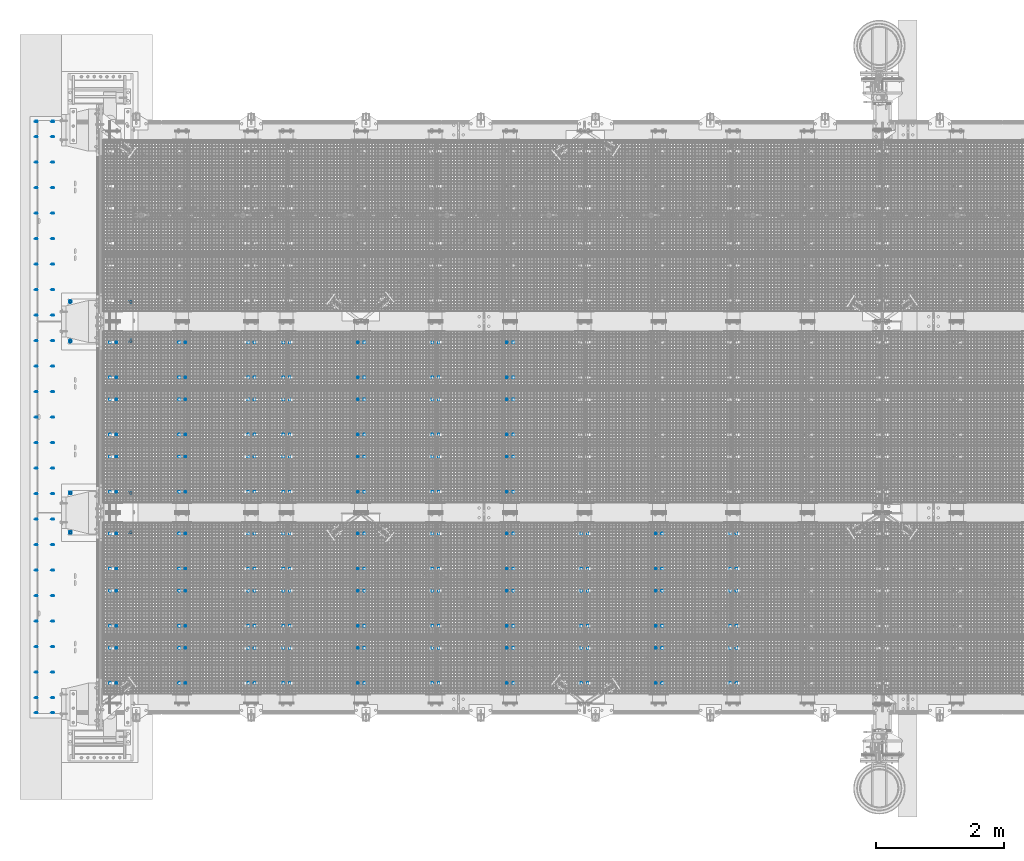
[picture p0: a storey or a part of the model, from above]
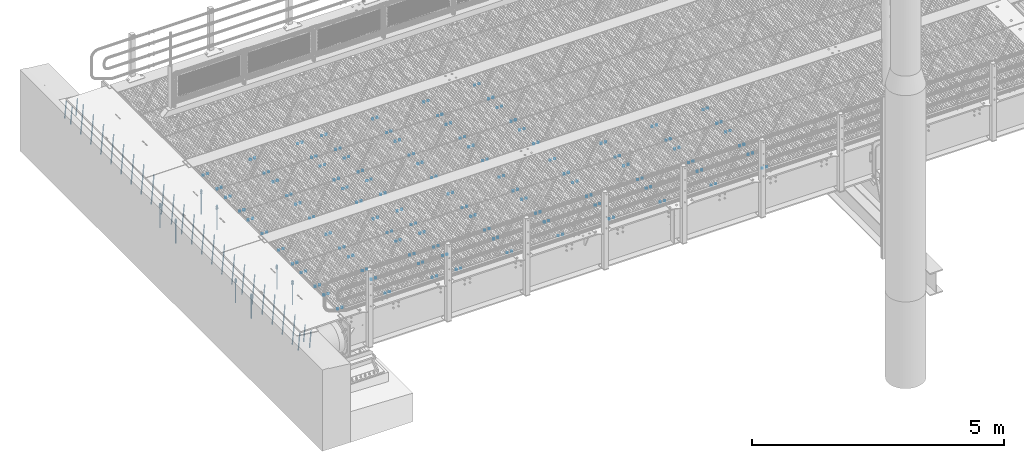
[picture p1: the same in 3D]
Properties of the parts of a building model (IFC2X3), part 1 of 2

# File
Description: ViewDefinition[CoordinationView_V2.0], ExchangeRequirement[Structural, SurfaceGeometry], Option [GridExport:On], Option [Assemblies:Off], Option [Bolts:On], Option [Rebars:On], Option [PourObjects:Off], Option [Welds:Off], Option [SurfaceTreatments:On], Option [LocationBy:0], Option [ViewColors:Off], Option [SectionedSpine:Off], Option [PropertySets:On], Option [Export all:Off]
File name: Brattvåg 9x18 ferjekaibru med gitterrister_2026-06-01.ifc
Time: 2026-06-01T10:39:22
Author: NORCONSULTAD\egj
Organization: Structural Designer
Written by: IFC Parser Version: 3.14.0
Made in: Tekla Structures 2025 Service Pack 6, IFC Export Version: 4.0.0.0 Dec 9 2025

# IfcBuildingStorey, Undefined
In: Undefined
Elevation: 0 mm

# IfcBeam: 12*12 (8)
In: Undefined
Description: 12*12; Material: STEEL/S355N
Tekla Common - Class: 5; Phase: 13
Tekla Quantity - Width: 12 mm; Height: 12 mm; Volume: 0 m3
BeamBaseQuantities - OuterSurfaceArea: 0 m2; NetVolume: 0 m3
Name | Top elevation | Bottom elevation | Tekla Quantity, Length (mm) = BeamBaseQuantities, Length (mm) | Net surface area (m2) | Area per tons (m2) | Gross footprint area (m2) | Weight (kg) | NetWeight (kg) | Slope (rad)
4 x STÅLBJELKE | -0.358 | -0.532 | 174 | 0.009 | 43.927 | 0 | 0.2 | 0.2 | 1.5708
2 x STÅLBJELKE | -0.532 | -0.544 | 625 | 0.03 | 42.87 | 0.008 | 0.71 | 0.7 | 0
2 x STÅLBJELKE | -0.346 | -0.358 | 625 | 0.03 | 42.87 | 0.008 | 0.71 | 0.7 | 0

# IfcBeam: 120*5 (1503)
In: Undefined
Description: 120*5; Material: STEEL/S355J2
Tekla Common - Class: 3; Phase: 3; Top elevation: +0.000; Bottom elevation: -0.120
Tekla Quantity - Width: 5 mm; Height: 120 mm
BeamBaseQuantities - NetVolume: 0 m3
Pset_BeamCommon - Slope: 0 rad
Name | Tekla Quantity, Length (mm) = BeamBaseQuantities, Length (mm) | Net surface area (m2) | Area per tons (m2) | Gross footprint area (m2) | Volume (m3) | Weight (kg) | OuterSurfaceArea (m2) | NetWeight (kg)
153 x GRATING | 535 | 0.135 | 54.618 | 0.002 | 0 | 2.47 | 0.1 | 2.5
18 x GRATING | 545 | 0.137 | 53.546 | 0.003 | 0 | 2.57 | 0.1 | 2.6
135 x GRATING | 878 | 0.221 | 53.369 | 0.004 | 0.001 | 4.14 | 0.2 | 4.1
918 x GRATING | 2320 | 0.581 | 54.31 | 0.01 | 0.001 | 10.7 | 0.6 | 10.7
108 x GRATING | 2330 | 0.584 | 53.188 | 0.012 | 0.001 | 10.97 | 0.6 | 11
153 x GRATING | 2298 | 0.575 | 54.344 | 0.01 | 0.001 | 10.59 | 0.6 | 10.7
18 x GRATING | 2308 | 0.578 | 53.209 | 0.012 | 0.001 | 10.86 | 0.6 | 11

# IfcBeam: 20*300 (2)
In: Undefined
Description: 20*300; Material: STEEL/S355N
Tekla Common - Class: 4; Phase: 10; Top elevation: -0.015; Bottom elevation: -0.185
Tekla Quantity - Length: 958.6 mm; Width: 300 mm; Height: 20 mm; Net surface area: 0.627 m2; Area per tons: 13.855 m2; Gross footprint area: 0 m2; Volume: 0.006 m3; Weight: 45.27 kg
BeamBaseQuantities - Length: 958.6 mm; OuterSurfaceArea: 0.6 m2; NetVolume: 0 m3; NetWeight: 45.3 kg
Pset_BeamCommon - Slope: 0 rad

# IfcBeam: 25*5 (3276)
In: Undefined
Description: 25*5; Material: STEEL/S355J2
Tekla Common - Class: 3; Phase: 3; Top elevation: +0.000; Bottom elevation: -0.025
Tekla Quantity - Width: 5 mm; Height: 25 mm; Volume: 0 m3
BeamBaseQuantities - NetVolume: 0 m3
Pset_BeamCommon - Slope: 0 rad
Name | Tekla Quantity, Length (mm) = BeamBaseQuantities, Length (mm) | Net surface area (m2) | Area per tons (m2) | Gross footprint area (m2) | Weight (kg) | OuterSurfaceArea (m2) | NetWeight (kg)
2844 x GRATING | 878 | 0.053 | 61.437 | 0.004 | 0.86 | 0.1 | 0.9
288 x GRATING | 141.5 | 0.009 | 62.947 | 0.001 | 0.14 | 0 | 0.1
144 x GRATING | 505 | 0.031 | 61.651 | 0.003 | 0.5 | 0 | 0.5

# IfcBeam: 60*10 (9)
In: Undefined
Description: 60*10; Material: STEEL/S355J2
Tekla Common - Class: 3; Phase: 3; Top elevation: -0.100; Bottom elevation: -0.160
Tekla Quantity - Length: 888 mm; Width: 10 mm; Height: 60 mm; Net surface area: 0.126 m2; Area per tons: 30.011 m2; Gross footprint area: 0.01 m2; Volume: 0.001 m3; Weight: 4.18 kg
BeamBaseQuantities - Length: 888 mm; OuterSurfaceArea: 0.1 m2; NetVolume: 0 m3; NetWeight: 4.1 kg
Pset_BeamCommon - Slope: 0 rad

# IfcBeam: CFCHS130*29 (52)
In: Undefined
Description: CFCHS130*29; Material: STEEL/EN 1.4462
Tekla Common - Class: 6; Phase: 4
Tekla Quantity - Length: 10 mm; Width: 130 mm; Height: 130 mm; Net surface area: 0.016 m2; Area per tons: 21.625 m2; Gross footprint area: 0 m2; Volume: 0 m3; Weight: 0.73 kg
BeamBaseQuantities - Length: 10 mm; OuterSurfaceArea: 0 m2; NetVolume: 0 m3; NetWeight: 0.7 kg
Pset_BeamCommon - Slope: 0 rad
Name | Top elevation | Bottom elevation
48 x BEAM | -0.380 | -0.510
4 x BEAM | -0.360 | -0.490

# IfcBeam: D10 (2)
In: Undefined
Description: D10; Material: STEEL/Steel_Undefined
Tekla Common - Class: 3; Phase: 6; Top elevation: +0.208; Bottom elevation: +0.068
Tekla Quantity - Length: 311.4 mm; Width: 10 mm; Height: 10 mm; Net surface area: 0.009 m2; Area per tons: 55.326 m2; Gross footprint area: 0 m2; Volume: 0 m3; Weight: 0.19 kg
BeamBaseQuantities - Length: 311.4 mm; OuterSurfaceArea: 0 m2; NetVolume: 0 m3; NetWeight: 0.2 kg
Pset_BeamCommon - Slope: 0 rad

# IfcBeam: D100 (4)
In: Undefined
Description: D100; Material: STEEL/Steel_Undefined
Tekla Common - Class: 3; Phase: 6; Top elevation: +5.449; Bottom elevation: +5.349
Tekla Quantity - Length: 15 mm; Width: 100 mm; Height: 100 mm; Net surface area: 0.013 m2; Area per tons: 40.078 m2; Gross footprint area: 0 m2; Volume: 0 m3; Weight: 0.36 kg
BeamBaseQuantities - Length: 15 mm; OuterSurfaceArea: 0 m2; NetVolume: 0 m3; NetWeight: 0.3 kg
Pset_BeamCommon - Slope: 0 rad

# IfcBeam: D110 (4)
In: Undefined
Description: D110; Material: STEEL/Steel_Undefined
Tekla Common - Class: 3; Phase: 6; Top elevation: +0.185; Bottom elevation: +0.075
Tekla Quantity - Length: 15 mm; Width: 110 mm; Height: 110 mm; Net surface area: 0.024 m2; Area per tons: 21.675 m2; Gross footprint area: 0 m2; Volume: 0 m3; Weight: 1.1 kg
BeamBaseQuantities - Length: 15 mm; OuterSurfaceArea: 0 m2; NetVolume: 0 m3; NetWeight: 1.1 kg
Pset_BeamCommon - Slope: 0 rad

# IfcBeam: D160 (2)
In: Undefined
Description: D160; Material: MISCELLANEOUS/UNDEFINED
Tekla Common - Class: 4; Phase: 7; Top elevation: -0.843; Bottom elevation: -1.003
Tekla Quantity - Length: 125 mm; Width: 160 mm; Height: 160 mm; Net surface area: 0.102 m2; Area per tons: 0 m2; Gross footprint area: 0 m2; Volume: 0.002 m3; Weight: 0 kg
BeamBaseQuantities - Length: 125 mm; OuterSurfaceArea: 0.1 m2; NetVolume: 0 m3; NetWeight: 0 kg
Pset_BeamCommon - Slope: 0 rad

# IfcBeam: D20 (3)
In: Undefined
Description: D20; Material: STEEL/S355N
Tekla Common - Class: 4; Phase: 11; Top elevation: -0.025; Bottom elevation: -0.045
Tekla Quantity - Width: 20 mm; Height: 20 mm; Gross footprint area: 0 m2; Volume: 0.001 m3
BeamBaseQuantities - OuterSurfaceArea: 0.2 m2; NetVolume: 0 m3
Pset_BeamCommon - Slope: 0 rad
Name | Tekla Quantity, Length (mm) = BeamBaseQuantities, Length (mm) | Net surface area (m2) | Area per tons (m2) | Weight (kg) | NetWeight (kg)
2 x STÅLBJELKE | 3145 | 0.193 | 27.658 | 6.98 | 7
STÅLBJELKE | 2990 | 0.184 | 27.662 | 6.64 | 6.6

# IfcBeam: D200 (6)
In: Undefined
Description: D200
Tekla Quantity - Width: 200 mm
BeamBaseQuantities - NetVolume: 0 m3
Name | Material | Class | Phase | Top elevation | Bottom elevation | Tekla Quantity, Length (mm) = BeamBaseQuantities, Length (mm) | Height (mm) | Net surface area (m2) | Area per tons (m2) | Gross footprint area (m2) | Volume (m3) | Weight (kg) | OuterSurfaceArea (m2) | NetWeight (kg) | Slope (rad)
2 x HEISTÅRN | STEEL/Steel_Undefined | 3 | 6 | +5.249 | +5.199 | 50 | 200 | 0.093 | 7.665 | 0.031 | 0.002 | 12.19 | 0.1 | 12.2 | 1.5708
2 x STÅLBJELKE | STEEL/S355N | 2 | 5 | -0.828 | -1.028 | 770 | 200 | 0.521 | 3.171 | 0 | 0.022 | 164.23 | 0.5 | 164.2 | 0
2 x STÅLBJELKE | STEEL/S355N | 2 | 5 | -0.890 | -1.028 | 280 | 138 | 0.207 | 4.108 | 0.051 | 0.006 | 50.33 | 0.2 | 50.3 | 0

# IfcBeam: D3 (535)
In: Undefined
Description: D3; Material: STEEL/S235J0
Tekla Common - Class: 3; Phase: 9
Tekla Quantity - Width: 3 mm; Height: 2.6 mm; Volume: 0 m3
BeamBaseQuantities - OuterSurfaceArea: 0 m2; NetVolume: 0 m3
Name | Top elevation | Bottom elevation | Tekla Quantity, Length (mm) = BeamBaseQuantities, Length (mm) | Net surface area (m2) | Area per tons (m2) | Gross footprint area (m2) | Weight (kg) | NetWeight (kg) | Slope (rad)
26 x BEAM | +0.866 | +0.373 | 493 | 0.004 | 196.644 | 0 | 0.02 | 0 | 1.5708
BEAM | +0.394 | +0.391 | 921.4 | 0.008 | 196.404 | 0.001 | 0.04 | 0 | 0
BEAM | +0.429 | +0.426 | 921.4 | 0.008 | 196.404 | 0.001 | 0.04 | 0 | 0
BEAM | +0.464 | +0.461 | 921.4 | 0.008 | 196.404 | 0.001 | 0.04 | 0 | 0
BEAM | +0.499 | +0.496 | 921.4 | 0.008 | 196.404 | 0.001 | 0.04 | 0 | 0
BEAM | +0.534 | +0.531 | 921.4 | 0.008 | 196.404 | 0.001 | 0.04 | 0 | 0
BEAM | +0.569 | +0.566 | 921.4 | 0.008 | 196.404 | 0.001 | 0.04 | 0 | 0
BEAM | +0.604 | +0.601 | 921.4 | 0.008 | 196.404 | 0.001 | 0.04 | 0 | 0
BEAM | +0.639 | +0.636 | 921.4 | 0.008 | 196.404 | 0.001 | 0.04 | 0 | 0
BEAM | +0.674 | +0.671 | 921.4 | 0.008 | 196.404 | 0.001 | 0.04 | 0 | 0
BEAM | +0.709 | +0.706 | 921.4 | 0.008 | 196.404 | 0.001 | 0.04 | 0 | 0
BEAM | +0.744 | +0.741 | 921.4 | 0.008 | 196.404 | 0.001 | 0.04 | 0 | 0
BEAM | +0.779 | +0.776 | 921.4 | 0.008 | 196.404 | 0.001 | 0.04 | 0 | 0
BEAM | +0.814 | +0.811 | 921.4 | 0.008 | 196.404 | 0.001 | 0.04 | 0 | 0
BEAM | +0.849 | +0.846 | 921.4 | 0.008 | 196.404 | 0.001 | 0.04 | 0 | 0
369 x BEAM | +0.867 | +0.374 | 493 | 0.004 | 196.644 | 0 | 0.02 | 0 | 1.5708
9 x BEAM | +0.394 | +0.391 | 1423 | 0.013 | 196.307 | 0.002 | 0.07 | 0.1 | 0
9 x BEAM | +0.429 | +0.426 | 1423 | 0.013 | 196.307 | 0.002 | 0.07 | 0.1 | 0
9 x BEAM | +0.464 | +0.461 | 1423 | 0.013 | 196.307 | 0.002 | 0.07 | 0.1 | 0
9 x BEAM | +0.499 | +0.496 | 1423 | 0.013 | 196.307 | 0.002 | 0.07 | 0.1 | 0
9 x BEAM | +0.534 | +0.531 | 1423 | 0.013 | 196.307 | 0.002 | 0.07 | 0.1 | 0
9 x BEAM | +0.569 | +0.566 | 1423 | 0.013 | 196.307 | 0.002 | 0.07 | 0.1 | 0
9 x BEAM | +0.604 | +0.601 | 1423 | 0.013 | 196.307 | 0.002 | 0.07 | 0.1 | 0
9 x BEAM | +0.639 | +0.636 | 1423 | 0.013 | 196.307 | 0.002 | 0.07 | 0.1 | 0
9 x BEAM | +0.674 | +0.671 | 1423 | 0.013 | 196.307 | 0.002 | 0.07 | 0.1 | 0
9 x BEAM | +0.709 | +0.706 | 1423 | 0.013 | 196.307 | 0.002 | 0.07 | 0.1 | 0
9 x BEAM | +0.744 | +0.741 | 1423 | 0.013 | 196.307 | 0.002 | 0.07 | 0.1 | 0
9 x BEAM | +0.779 | +0.776 | 1423 | 0.013 | 196.307 | 0.002 | 0.07 | 0.1 | 0
9 x BEAM | +0.814 | +0.811 | 1423 | 0.013 | 196.307 | 0.002 | 0.07 | 0.1 | 0
9 x BEAM | +0.849 | +0.846 | 1423 | 0.013 | 196.307 | 0.002 | 0.07 | 0.1 | 0

# IfcBeam: D30 (4)
In: Undefined
Description: D30; Material: STEEL/Steel_Undefined
Tekla Common - Class: 3; Phase: 6; Top elevation: +0.145; Bottom elevation: +0.115
Tekla Quantity - Length: 15 mm; Width: 30 mm; Height: 30 mm; Net surface area: 0.003 m2; Area per tons: 34.569 m2; Gross footprint area: 0 m2; Volume: 0 m3; Weight: 0.07 kg
BeamBaseQuantities - Length: 15 mm; OuterSurfaceArea: 0 m2; NetVolume: 0 m3; NetWeight: 0.1 kg
Pset_BeamCommon - Slope: 0 rad

# IfcBeam: D32 (30)
In: Undefined
Description: D32; Material: STEEL/Steel_Undefined
Tekla Common - Class: 3; Phase: 6
Tekla Quantity - Width: 32 mm; Height: 32 mm; Gross footprint area: 0 m2; Volume: 0 m3; Weight: 2.04 kg
BeamBaseQuantities - OuterSurfaceArea: 0 m2; NetVolume: 0 m3; NetWeight: 2 kg
Name | Top elevation | Bottom elevation | Tekla Quantity, Length (mm) = BeamBaseQuantities, Length (mm) | Net surface area (m2) | Area per tons (m2) | Slope (rad)
2 x HEISTÅRN | +0.389 | +0.230 | 243.2 | 0.035 | 17.341 | 0.04047
2 x HEISTÅRN | +0.580 | +0.421 | 243.2 | 0.035 | 17.341 | 0.04047
2 x HEISTÅRN | +0.772 | +0.612 | 243.2 | 0.035 | 17.341 | 0.04047
2 x HEISTÅRN | +0.963 | +0.803 | 243.2 | 0.035 | 17.341 | 0.04047
2 x HEISTÅRN | +1.154 | +0.994 | 243.2 | 0.035 | 17.341 | 0.04047
2 x HEISTÅRN | +1.345 | +1.186 | 243.2 | 0.035 | 17.341 | 0.04047
2 x HEISTÅRN | +1.536 | +1.377 | 243.2 | 0.035 | 17.341 | 0.04047
2 x HEISTÅRN | +0.485 | +0.326 | 242.8 | 0.034 | 16.588 | 0.08742
2 x HEISTÅRN | +0.676 | +0.517 | 242.8 | 0.034 | 16.588 | 0.08742
2 x HEISTÅRN | +0.867 | +0.708 | 242.8 | 0.034 | 16.588 | 0.08742
2 x HEISTÅRN | +1.058 | +0.899 | 242.8 | 0.034 | 16.588 | 0.08742
2 x HEISTÅRN | +1.250 | +1.090 | 242.8 | 0.034 | 16.588 | 0.08742
2 x HEISTÅRN | +1.441 | +1.281 | 242.8 | 0.034 | 16.588 | 0.08742
2 x HEISTÅRN | +1.632 | +1.472 | 242.8 | 0.034 | 16.588 | 0.08742
2 x HEISTÅRN | +1.727 | +1.568 | 243.2 | 0.035 | 17.341 | 0.04047

# IfcBeam: D38 (4)
In: Undefined
Description: D38; Material: STEEL/Steel_Undefined
Tekla Common - Class: 3; Phase: 6
Tekla Quantity - Length: 420.3 mm; Width: 38 mm; Height: 38 mm; Net surface area: 0.063 m2; Area per tons: 13.938 m2; Gross footprint area: 0 m2; Volume: 0.001 m3; Weight: 4.54 kg
BeamBaseQuantities - Length: 420.3 mm; OuterSurfaceArea: 0.1 m2; NetVolume: 0 m3; NetWeight: 4.5 kg
Pset_BeamCommon - Slope: 0.08971 rad
Name | Top elevation | Bottom elevation
2 x HEISTÅRN | +0.309 | +0.066
2 x HEISTÅRN | +1.900 | +1.657

# IfcBeam: D488 (2)
In: Undefined
Description: D488; Material: STEEL/S355N
Tekla Common - Class: 4; Phase: 10; Top elevation: -0.015; Bottom elevation: -0.503
Tekla Quantity - Length: 20 mm; Width: 298 mm; Height: 488 mm; Net surface area: 0.265 m2; Area per tons: 14.182 m2; Gross footprint area: 0 m2; Volume: 0.002 m3; Weight: 18.7 kg
BeamBaseQuantities - Length: 20 mm; OuterSurfaceArea: 0.3 m2; NetVolume: 0 m3; NetWeight: 18.7 kg
Pset_BeamCommon - Slope: 0.00024 rad

# IfcBeam: D60, STÅLBJELKE
In: Undefined
Description: D60; Material: STEEL/S355J2+N
Tekla Common - Class: 4; Phase: 10; Top elevation: -0.453; Bottom elevation: -0.513
Tekla Quantity - Length: 9000 mm; Width: 60 mm; Height: 60 mm; Net surface area: 1.691 m2; Area per tons: 8.687 m2; Gross footprint area: 0 m2; Volume: 0.025 m3; Weight: 194.66 kg
BeamBaseQuantities - Length: 9000 mm; OuterSurfaceArea: 1.7 m2; NetVolume: 0 m3; NetWeight: 194.7 kg
Pset_BeamCommon - Slope: 0 rad

# IfcBeam: D70 (30)
In: Undefined
Description: D70
Tekla Quantity - Width: 70 mm; Height: 70 mm; Gross footprint area: 0 m2
BeamBaseQuantities - OuterSurfaceArea: 0 m2; NetVolume: 0 m3
Pset_BeamCommon - Slope: 0 rad
Name | Material | Class | Phase | Top elevation | Bottom elevation | Tekla Quantity, Length (mm) = BeamBaseQuantities, Length (mm) | Net surface area (m2) | Area per tons (m2) | Volume (m3) | Weight (kg) | NetWeight (kg)
24 x BEAM | STEEL/EN 1.4462 | 6 | 4 | -0.410 | -0.480 | 200 | 0.048 | 8.237 | 0.001 | 5.79 | 5.8
2 x BEAM | STEEL/EN 1.4462 | 6 | 4 | -0.390 | -0.460 | 200 | 0.048 | 8.237 | 0.001 | 5.79 | 5.8
2 x HEISTÅRN | STEEL/Steel_Undefined | 3 | 6 | +0.175 | +0.105 | 140 | 0.038 | 9.242 | 0.001 | 4.12 | 4.1
2 x HEISTÅRN | STEEL/Steel_Undefined | 3 | 6 | +1.862 | +1.792 | 130 | 0.036 | 9.382 | 0 | 3.84 | 3.8

# IfcBeam: D708 (2)
In: Undefined
Description: D708; Material: STEEL/Steel_Undefined
Tekla Common - Class: 3; Phase: 6; Top elevation: +6.270; Bottom elevation: +6.260
Tekla Quantity - Length: 10 mm; Width: 708 mm; Height: 708 mm; Net surface area: 0.807 m2; Area per tons: 26.199 m2; Gross footprint area: 0.392 m2; Volume: 0.004 m3; Weight: 30.8 kg
BeamBaseQuantities - Length: 10 mm; OuterSurfaceArea: 0.8 m2; NetVolume: 0 m3; NetWeight: 30.8 kg
Pset_BeamCommon - Slope: 1.5708 rad

# IfcBeam: D78 (2)
In: Undefined
Description: D78; Material: STEEL/Steel_Undefined
Tekla Common - Class: 3; Phase: 6; Top elevation: +5.438; Bottom elevation: +5.360
Tekla Quantity - Length: 250 mm; Width: 78 mm; Height: 78 mm; Net surface area: 0.07 m2; Area per tons: 7.68 m2; Gross footprint area: 0 m2; Volume: 0.001 m3; Weight: 9.14 kg
BeamBaseQuantities - Length: 250 mm; OuterSurfaceArea: 0.1 m2; NetVolume: 0 m3; NetWeight: 9.1 kg
Pset_BeamCommon - Slope: 0 rad

# IfcBeam: D80 (4)
In: Undefined
Description: D80; Material: STEEL/Steel_Undefined
Tekla Common - Class: 3; Phase: 6
Tekla Quantity - Width: 80 mm; Height: 80 mm; Gross footprint area: 0 m2
BeamBaseQuantities - NetVolume: 0 m3
Name | Top elevation | Bottom elevation | Tekla Quantity, Length (mm) = BeamBaseQuantities, Length (mm) | Net surface area (m2) | Area per tons (m2) | Volume (m3) | Weight (kg) | OuterSurfaceArea (m2) | NetWeight (kg) | Slope (rad)
2 x HEISTÅRN | +0.170 | +0.090 | 170 | 0.053 | 7.993 | 0.001 | 6.54 | 0.1 | 6.5 | 0
2 x HEISTÅRN | +5.199 | +0.205 | 4993.9 | 1.257 | 6.545 | 0.024 | 192.02 | 1.3 | 192 | 1.55878

# IfcBeam: D800 (4)
In: Undefined
Description: D800; Material: MISCELLANEOUS/NULLVEKT
Tekla Common - Class: 4; Phase: 12; Top elevation: -0.115; Bottom elevation: -0.915
Tekla Quantity - Length: 25 mm; Width: 800 mm; Height: 800 mm; Net surface area: 1.065 m2; Area per tons: 0 m2; Gross footprint area: 0 m2; Volume: 0.014 m3; Weight: 0 kg
BeamBaseQuantities - Length: 25 mm; OuterSurfaceArea: 1.1 m2; NetVolume: 0 m3; NetWeight: 0 kg
Pset_BeamCommon - Slope: 0 rad

# IfcBeam: ELD70*70*65*65 (2)
In: Undefined
Description: ELD70*70*65*65; Material: STEEL/Steel_Undefined
Tekla Common - Class: 3; Phase: 6; Top elevation: +0.175; Bottom elevation: +0.105
Tekla Quantity - Length: 10 mm; Width: 70 mm; Height: 70 mm; Net surface area: 0.009 m2; Area per tons: 33.422 m2; Gross footprint area: 0 m2; Volume: 0 m3; Weight: 0.27 kg
BeamBaseQuantities - Length: 10 mm; OuterSurfaceArea: 0 m2; NetVolume: 0 m3; NetWeight: 0.3 kg
Pset_BeamCommon - Slope: 0 rad

# IfcBeam: EPD660*660*490*490*100 (4)
In: Undefined
Description: EPD660*660*490*490*100; Material: MISCELLANEOUS/NULLVEKT
Tekla Common - Class: 4; Phase: 12; Top elevation: -0.185; Bottom elevation: -0.845
Tekla Quantity - Length: 350 mm; Width: 660 mm; Height: 660 mm; Net surface area: 0.808 m2; Area per tons: 0 m2; Gross footprint area: 0 m2; Volume: 0.053 m3; Weight: 0 kg
BeamBaseQuantities - Length: 350 mm; OuterSurfaceArea: 0.8 m2; NetVolume: 0.1 m3; NetWeight: 0 kg
Pset_BeamCommon - Slope: 0 rad

# IfcBeam: HEA600, STÅLBJELKE
In: Undefined
Description: HEA600; Material: STEEL/S355J2+N
Tekla Common - Class: 5; Phase: 13; Top elevation: -0.890; Bottom elevation: -1.480
Tekla Quantity - Length: 10130 mm; Width: 300 mm; Height: 590 mm; Net surface area: 23.884 m2; Area per tons: 12.981 m2; Gross footprint area: 3.022 m2; Volume: 0.229 m3; Weight: 1801.14 kg
BeamBaseQuantities - Length: 10130 mm; OuterSurfaceArea: 23.4 m2; NetVolume: 0.2 m3; NetWeight: 1747.7 kg
Pset_BeamCommon - Slope: 0 rad

# IfcBeam: HEA900 (4)
In: Undefined
Description: HEA900; Material: STEEL/S355J2+N
Tekla Common - Class: 2; Phase: 5; Top elevation: +0.000; Bottom elevation: -0.890
Tekla Quantity - Length: 16807 mm; Width: 300 mm; Height: 890 mm; Net surface area: 49.61 m2; Area per tons: 11.509 m2; Gross footprint area: 5.042 m2; Volume: 0.54 m3; Weight: 4235.11 kg
BeamBaseQuantities - Length: 16807 mm; OuterSurfaceArea: 48.7 m2; NetVolume: 0.5 m3; NetWeight: 4126.9 kg
Pset_BeamCommon - Slope: 0 rad

# IfcBeam: HEB180 (13)
In: Undefined
Description: HEB180; Material: STEEL/S355J2+N
Tekla Common - Class: 3; Phase: 4; Top elevation: -0.355; Bottom elevation: -0.535
Tekla Quantity - Width: 180 mm; Height: 180 mm; Area per tons: 20.246 m2
BeamBaseQuantities - NetVolume: 0 m3
Pset_BeamCommon - Slope: 0 rad
Name | Tekla Quantity, Length (mm) = BeamBaseQuantities, Length (mm) | Net surface area (m2) | Gross footprint area (m2) | Volume (m3) | Weight (kg) | OuterSurfaceArea (m2) | NetWeight (kg)
2 x STÅLBJELKE | 4354.3 | 4.641 | 0.784 | 0.028 | 223.03 | 4.5 | 216.4
2 x STÅLBJELKE | 3414.8 | 3.643 | 0.615 | 0.022 | 174.91 | 3.5 | 169.7
5 x STÅLBJELKE | 2200 | 2.351 | 0.396 | 0.014 | 112.69 | 2.3 | 109.4
2 x STÅLBJELKE | 3853.3 | 4.109 | 0.694 | 0.025 | 197.37 | 4 | 191.5
2 x STÅLBJELKE | 4051.6 | 4.32 | 0.729 | 0.026 | 207.53 | 4.2 | 201.4

# IfcBeam: HEB200 (50)
In: Undefined
Description: HEB200; Material: STEEL/S355J2+N
Tekla Quantity - Width: 200 mm; Height: 200 mm; Area per tons: 18.779 m2
BeamBaseQuantities - NetVolume: 0 m3
Pset_BeamCommon - Slope: 0 rad
Name | Class | Phase | Top elevation | Bottom elevation | Tekla Quantity, Length (mm) = BeamBaseQuantities, Length (mm) | Net surface area (m2) | Gross footprint area (m2) | Volume (m3) | Weight (kg) | OuterSurfaceArea (m2) | NetWeight (kg)
2 x STÅLBJELKE | 5 | 13 | -0.345 | -0.545 | 387 | 0.472 | 0.077 | 0.003 | 23.72 | 0.3 | 22.9
48 x STÅLBJELKE | 4 | 2 | -0.120 | -0.320 | 2954 | 3.507 | 0.591 | 0.023 | 181.06 | 3.5 | 174.6

# IfcBeam: HEB550, BEAM
In: Undefined
Description: HEB550; Material: STEEL/Steel_Undefined
Tekla Common - Class: 3; Phase: 6; Top elevation: -2.326; Bottom elevation: -2.876
Tekla Quantity - Length: 12497 mm; Width: 300 mm; Height: 550 mm; Net surface area: 28.418 m2; Area per tons: 11.15 m2; Gross footprint area: 3.749 m2; Volume: 0.318 m3; Weight: 2492.76 kg
BeamBaseQuantities - Length: 12497 mm; OuterSurfaceArea: 27.8 m2; NetVolume: 0.3 m3; NetWeight: 2431 kg
Pset_BeamCommon - Slope: 0 rad

# IfcBeam: L100*65*10 (3)
In: Undefined
Description: L100*65*10; Material: STEEL/S355J2
Tekla Common - Class: 4; Phase: 10; Top elevation: -0.130; Bottom elevation: -0.230
Tekla Quantity - Length: 2660 mm; Width: 65 mm; Height: 100 mm; Net surface area: 0.881 m2; Area per tons: 26.213 m2; Gross footprint area: 0.027 m2; Volume: 0.004 m3; Weight: 32.57 kg
BeamBaseQuantities - Length: 2660 mm; OuterSurfaceArea: 0.8 m2; NetVolume: 0 m3; NetWeight: 32.4 kg
Pset_BeamCommon - Slope: 0 rad

# IfcBeam: L60*6 (9)
In: Undefined
Description: L60*6; Material: STEEL/S355J2
Tekla Common - Class: 4; Phase: 10; Top elevation: -0.185; Bottom elevation: -0.245
Tekla Quantity - Length: 2660 mm; Width: 60 mm; Height: 60 mm; Net surface area: 0.64 m2; Area per tons: 42.954 m2; Gross footprint area: 0.16 m2; Volume: 0.002 m3; Weight: 14.43 kg
BeamBaseQuantities - Length: 2660 mm; OuterSurfaceArea: 0.6 m2; NetVolume: 0 m3; NetWeight: 14.3 kg
Pset_BeamCommon - Slope: 0 rad

# IfcBeam: PL20*251 (2)
In: Undefined
Description: PL20*251; Material: STEEL/S355N
Tekla Common - Class: 4; Phase: 10; Top elevation: -0.031; Bottom elevation: -0.484
Tekla Quantity - Length: 453 mm; Width: 20 mm; Height: 251 mm; Net surface area: 0.202 m2; Area per tons: 14.465 m2; Gross footprint area: 0 m2; Volume: 0.002 m3; Weight: 13.93 kg
BeamBaseQuantities - Length: 453 mm; OuterSurfaceArea: 0.2 m2; NetVolume: 0 m3; NetWeight: 13.9 kg
Pset_BeamCommon - Slope: 1.57042 rad

# IfcBeam: PL3*1000 (2)
In: Undefined
Description: PL3*1000; Material: STEEL/S355J2+N
Tekla Common - Class: 4; Phase: 9; Top elevation: +1.187; Bottom elevation: +0.187
Tekla Quantity - Length: 153.7 mm; Width: 3 mm; Height: 1000 mm; Net surface area: 0.314 m2; Area per tons: 86.902 m2; Gross footprint area: 0 m2; Volume: 0 m3; Weight: 3.63 kg
BeamBaseQuantities - Length: 153.7 mm; OuterSurfaceArea: 0.3 m2; NetVolume: 0 m3; NetWeight: 3.6 kg
Pset_BeamCommon - Slope: 0 rad

# IfcBeam: PL3*35 (40)
In: Undefined
Description: PL3*35; Material: STEEL/S235J0
Tekla Common - Class: 120; Phase: 9
Tekla Quantity - Width: 3 mm; Height: 35 mm; Volume: 0 m3
BeamBaseQuantities - NetVolume: 0 m3
Name | Top elevation | Bottom elevation | Tekla Quantity, Length (mm) = BeamBaseQuantities, Length (mm) | Net surface area (m2) | Area per tons (m2) | Gross footprint area (m2) | Weight (kg) | OuterSurfaceArea (m2) | NetWeight (kg) | Slope (rad)
9 x STÅLBJELKE | +0.901 | +0.338 | 563 | 0.04 | 92.887 | 0 | 0.44 | 0 | 0.3 | 1.57079
9 x STÅLBJELKE | +0.901 | +0.339 | 562.9 | 0.04 | 92.888 | 0 | 0.44 | 0 | 0.3 | 1.5708
9 x STÅLBJELKE | +0.901 | +0.866 | 1493 | 0.111 | 92.452 | 0.004 | 1.2 | 0.1 | 1.2 | 0
STÅLBJELKE | +0.902 | +0.339 | 563 | 0.04 | 92.887 | 0 | 0.44 | 0 | 0.3 | 1.57079
STÅLBJELKE | +0.901 | +0.338 | 562.9 | 0.04 | 92.888 | 0 | 0.44 | 0 | 0.3 | 1.5708
STÅLBJELKE | +0.902 | +0.866 | 991.4 | 0.073 | 92.582 | 0.003 | 0.79 | 0.1 | 0.7 | 0.00006
9 x STÅLBJELKE | +0.374 | +0.338 | 1493 | 0.111 | 92.452 | 0.004 | 1.2 | 0.1 | 1.2 | 0.00004
STÅLBJELKE | +0.374 | +0.338 | 991.4 | 0.073 | 92.582 | 0.003 | 0.79 | 0.1 | 0.7 | 0

# IfcBeam: RHS100*10 (20)
In: Undefined
Description: RHS100*10; Material: STEEL/S355J2H
Tekla Common - Class: 11; Phase: 8; Top elevation: +1.010; Bottom elevation: -0.845
Tekla Quantity - Length: 1855 mm; Width: 100 mm; Height: 100 mm; Net surface area: 0.746 m2; Area per tons: 13.651 m2; Gross footprint area: 0.004 m2; Volume: 0.006 m3; Weight: 50.82 kg
BeamBaseQuantities - Length: 1855 mm; OuterSurfaceArea: 0.6 m2; NetVolume: 0 m3; NetWeight: 52.4 kg
Pset_BeamCommon - Slope: 1.5708 rad

# IfcBeam: RHS140*140*10 (2)
In: Undefined
Description: RHS140*140*10; Material: STEEL/S355J2H+N
Tekla Common - Class: 4; Phase: 9; Top elevation: +0.155; Bottom elevation: +0.015
Tekla Quantity - Width: 140 mm; Height: 140 mm
Pset_BeamCommon - Slope: 0 rad
Name | Tekla Quantity, Length (mm) = BeamBaseQuantities, Length (mm) | Net surface area (m2) | Area per tons (m2) | Gross footprint area (m2) | Volume (m3) | Weight (kg) | OuterSurfaceArea (m2) | NetVolume (m3) | NetWeight (kg)
STÅLBJELKE | 14992 | 8.334 | 13.731 | 2.062 | 0.077 | 606.96 | 8.3 | 0.1 | 607
STÅLBJELKE | 1301 | 0.667 | 13.868 | 0.164 | 0.006 | 48.1 | 0.6 | 0 | 48.1

# IfcBeam: Ø180*10 (2)
In: Undefined
Description: Ø180*10; Material: STEEL/Steel_Undefined
Tekla Common - Class: 3; Phase: 6; Top elevation: +5.200; Bottom elevation: +1.598
Tekla Quantity - Length: 3600 mm; Width: 180 mm; Height: 180 mm; Net surface area: 2.036 m2; Area per tons: 13.642 m2; Gross footprint area: 0 m2; Volume: 0.019 m3; Weight: 149.21 kg
BeamBaseQuantities - Length: 3600 mm; OuterSurfaceArea: 2 m2; NetVolume: 0 m3; NetWeight: 149.2 kg
Pset_BeamCommon - Slope: 1.55878 rad

# IfcBeam: Ø490*100 (4)
In: Undefined
Description: Ø490*100; Material: MISCELLANEOUS/NULLVEKT
Tekla Common - Class: 4; Phase: 12; Top elevation: -0.270; Bottom elevation: -0.760
Tekla Quantity - Length: 75 mm; Width: 490 mm; Height: 490 mm; Net surface area: 0.273 m2; Area per tons: 0 m2; Gross footprint area: 0 m2; Volume: 0.009 m3; Weight: 0 kg
BeamBaseQuantities - Length: 75 mm; OuterSurfaceArea: 0.3 m2; NetVolume: 0 m3; NetWeight: 0 kg
Pset_BeamCommon - Slope: 0 rad

# IfcBeam: Ø508*32, STÅLBJELKE
In: Undefined
Description: Ø508*32; Material: STEEL/S355J2H+N
Tekla Common - Class: 4; Phase: 10; Top elevation: -0.005; Bottom elevation: -0.513
Tekla Quantity - Length: 9300 mm; Width: 508 mm; Height: 508 mm; Net surface area: 14.751 m2; Area per tons: 4.284 m2; Gross footprint area: 0 m2; Volume: 0.439 m3; Weight: 3443.55 kg
BeamBaseQuantities - Length: 9300 mm; OuterSurfaceArea: 14.8 m2; NetVolume: 0.3 m3; NetWeight: 3443.5 kg
Pset_BeamCommon - Slope: 0 rad

# IfcBeam: Ø51*3.6 (40)
In: Undefined
Description: Ø51*3.6; Material: STEEL/S355J2H
Tekla Common - Class: 11; Phase: 8
Tekla Quantity - Length: 200 mm; Width: 51 mm; Height: 51 mm; Net surface area: 0.032 m2; Area per tons: 39.504 m2; Gross footprint area: 0 m2; Volume: 0 m3; Weight: 0.82 kg
BeamBaseQuantities - Length: 200 mm; OuterSurfaceArea: 0 m2; NetVolume: 0 m3; NetWeight: 0.7 kg
Pset_BeamCommon - Slope: 0 rad
Name | Top elevation | Bottom elevation
10 x STÅLBJELKE | +0.175 | +0.124
10 x STÅLBJELKE | +0.445 | +0.394
10 x STÅLBJELKE | +0.715 | +0.664
10 x STÅLBJELKE | +0.995 | +0.944

# IfcBeam: Ø60.3*3.6 (40)
In: Undefined
Description: Ø60.3*3.6; Material: STEEL/S355J2H
Tekla Common - Class: 11; Phase: 8
Tekla Quantity - Width: 60.3 mm; Height: 60.3 mm; Gross footprint area: 0 m2
BeamBaseQuantities - NetVolume: 0 m3
Pset_BeamCommon - Slope: 0 rad
Name | Top elevation | Bottom elevation | Tekla Quantity, Length (mm) = BeamBaseQuantities, Length (mm) | Net surface area (m2) | Area per tons (m2) | Volume (m3) | Weight (kg) | OuterSurfaceArea (m2) | NetWeight (kg)
6 x STÅLBJELKE | +0.180 | +0.119 | 4384 | 0.826 | 38.401 | 0.003 | 21.51 | 0.8 | 21.5
6 x STÅLBJELKE | +0.450 | +0.389 | 4384 | 0.826 | 38.401 | 0.003 | 21.51 | 0.8 | 21.5
6 x STÅLBJELKE | +0.720 | +0.659 | 4384 | 0.826 | 38.401 | 0.003 | 21.51 | 0.8 | 21.5
2 x STÅLBJELKE | +0.180 | +0.119 | 1190 | 0.225 | 38.484 | 0.001 | 5.84 | 0.2 | 5.8
2 x STÅLBJELKE | +0.450 | +0.389 | 1190 | 0.225 | 38.484 | 0.001 | 5.84 | 0.2 | 5.8
2 x STÅLBJELKE | +0.720 | +0.659 | 1190 | 0.225 | 38.484 | 0.001 | 5.84 | 0.2 | 5.8
2 x STÅLBJELKE | +1.000 | +0.119 | 2969.3 | 0.577 | 38.426 | 0.002 | 15.02 | 0.6 | 15
2 x STÅLBJELKE | +0.720 | +0.390 | 2240.9 | 0.44 | 38.444 | 0.001 | 11.44 | 0.3 | 11.3
2 x STÅLBJELKE | +1.000 | +0.119 | 3225.4 | 0.625 | 38.424 | 0.002 | 16.27 | 0.6 | 16.3
6 x STÅLBJELKE | +1.000 | +0.939 | 4384 | 0.826 | 38.401 | 0.003 | 21.51 | 0.8 | 21.5
2 x STÅLBJELKE | +1.000 | +0.939 | 1190 | 0.225 | 38.484 | 0.001 | 5.84 | 0.2 | 5.8
2 x STÅLBJELKE | +0.720 | +0.390 | 2209 | 0.434 | 38.444 | 0.001 | 11.29 | 0.3 | 11.3

# IfcBeam: Ø60.3*4.8 (35)
In: Undefined
Description: Ø60.3*4.8; Material: STEEL/S355J2H
Tekla Common - Class: 4; Phase: 9
Tekla Quantity - Width: 60.3 mm; Height: 60.3 mm
BeamBaseQuantities - NetVolume: 0 m3
Name | Top elevation | Bottom elevation | Tekla Quantity, Length (mm) = BeamBaseQuantities, Length (mm) | Net surface area (m2) | Area per tons (m2) | Gross footprint area (m2) | Volume (m3) | Weight (kg) | OuterSurfaceArea (m2) | NetWeight (kg) | Slope (rad)
2 x STÅLBJELKE | +1.987 | +0.225 | 1762 | 0.333 | 29.478 | 0.001 | 0.001 | 11.28 | 0.3 | 11.3 | 1.5708
11 x STÅLBJELKE | +0.915 | +0.155 | 760 | 0.144 | 29.582 | 0.001 | 0.001 | 4.87 | 0.1 | 4.9 | 1.5708
9 x STÅLBJELKE | +0.987 | +0.927 | 1530 | 0.289 | 29.49 | 0 | 0.001 | 9.8 | 0.3 | 9.8 | 0
9 x STÅLBJELKE | +0.315 | +0.255 | 1530 | 0.289 | 29.49 | 0 | 0.001 | 9.8 | 0.3 | 9.8 | 0
STÅLBJELKE | +0.915 | +0.340 | 575 | 0.109 | 29.64 | 0.001 | 0 | 3.68 | 0.1 | 3.7 | 1.5708
STÅLBJELKE | +0.987 | +0.927 | 1005 | 0.19 | 29.537 | 0 | 0.001 | 6.43 | 0.2 | 6.5 | 0
STÅLBJELKE | +0.315 | +0.255 | 1005 | 0.19 | 29.537 | 0 | 0.001 | 6.43 | 0.2 | 6.5 | 0
STÅLBJELKE | +0.255 | +0.155 | 100 | 0.02 | 30.784 | 0.001 | 0 | 0.64 | 0 | 0.7 | 1.5708

# IfcBeam: Ø660*115 (4)
In: Undefined
Description: Ø660*115; Material: MISCELLANEOUS/NULLVEKT
Tekla Common - Class: 4; Phase: 12; Top elevation: -0.185; Bottom elevation: -0.845
Tekla Quantity - Length: 125 mm; Width: 660 mm; Height: 660 mm; Net surface area: 0.497 m2; Area per tons: 0 m2; Gross footprint area: 0 m2; Volume: 0.025 m3; Weight: 0 kg
BeamBaseQuantities - Length: 125 mm; OuterSurfaceArea: 0.5 m2; NetVolume: 0 m3; NetWeight: 0 kg
Pset_BeamCommon - Slope: 0 rad

# IfcBeam: Ø70*16 (60)
In: Undefined
Description: Ø70*16; Material: STEEL/S355J2H
Tekla Common - Class: 3; Phase: 10
Tekla Quantity - Width: 70 mm; Height: 70 mm; Gross footprint area: 0 m2; Volume: 0 m3
BeamBaseQuantities - OuterSurfaceArea: 0 m2; NetVolume: 0 m3
Pset_BeamCommon - Slope: 0 rad
Name | Top elevation | Bottom elevation | Tekla Quantity, Length (mm) = BeamBaseQuantities, Length (mm) | Net surface area (m2) | Area per tons (m2) | Weight (kg) | NetWeight (kg)
4 x BEAM | -0.049 | -0.119 | 50 | 0.013 | 13.826 | 1.04 | 0.9
8 x BEAM | -0.250 | -0.320 | 150 | 0.036 | 11.624 | 3.11 | 3.1
8 x BEAM | -0.357 | -0.427 | 150 | 0.036 | 11.624 | 3.11 | 3.1
8 x BEAM | -0.464 | -0.534 | 150 | 0.036 | 11.624 | 3.11 | 3.1
8 x BEAM | -0.571 | -0.641 | 150 | 0.036 | 11.624 | 3.11 | 3.1
8 x BEAM | -0.678 | -0.748 | 150 | 0.036 | 11.624 | 3.11 | 3.1
8 x BEAM | -0.772 | -0.842 | 150 | 0.036 | 11.624 | 3.11 | 3.1
4 x BEAM | -0.049 | -0.119 | 150 | 0.036 | 11.624 | 3.11 | 3.1
4 x BEAM | -0.143 | -0.213 | 150 | 0.036 | 11.624 | 3.11 | 3.1

# IfcBeam: Ø708*12 (2)
In: Undefined
Description: Ø708*12; Material: STEEL/Steel_Undefined
Tekla Common - Class: 3; Phase: 6; Top elevation: +6.260; Bottom elevation: +6.110
Tekla Quantity - Length: 150 mm; Width: 708 mm; Height: 708 mm; Net surface area: 0.36 m2; Area per tons: 11.69 m2; Gross footprint area: 0.027 m2; Volume: 0.004 m3; Weight: 30.79 kg
BeamBaseQuantities - Length: 150 mm; OuterSurfaceArea: 0.3 m2; NetVolume: 0 m3; NetWeight: 30.8 kg
Pset_BeamCommon - Slope: 1.5708 rad

# IfcBeam: Ø73*5.5 (29)
In: Undefined
Description: Ø73*5.5; Material: STEEL/S355J2H
Tekla Common - Class: 7; Phase: 9
Tekla Quantity - Width: 73 mm; Volume: 0 m3
BeamBaseQuantities - NetVolume: 0 m3
Name | Top elevation | Bottom elevation | Tekla Quantity, Length (mm) = BeamBaseQuantities, Length (mm) | Height (mm) | Net surface area (m2) | Area per tons (m2) | Gross footprint area (m2) | Weight (kg) | OuterSurfaceArea (m2) | NetWeight (kg) | Slope (rad)
2 x STÅLBJELKE | +0.862 | +0.789 | 73 | 153 | 0.04 | 26 | 0.002 | 1.55 | 0 | 1.6 | 1.5708
2 x STÅLBJELKE | +0.422 | +0.349 | 73 | 153 | 0.04 | 26 | 0.002 | 1.55 | 0 | 1.6 | 1.5708
8 x STÅLBJELKE | +0.322 | +0.249 | 73 | 172 | 0.045 | 25.953 | 0.001 | 1.72 | 0 | 1.7 | 1.5708
8 x STÅLBJELKE | +0.993 | +0.873 | 120.5 | 168 | 0.053 | 26.021 | 0 | 2.02 | 0.1 | 2 | 1.57078
3 x STÅLBJELKE | +0.322 | +0.249 | 120.5 | 73 | 0.031 | 26.371 | 0.001 | 1.17 | 0 | 1.2 | 0
STÅLBJELKE | +0.370 | +0.249 | 95.5 | 73 | 0.036 | 26.512 | 0.001 | 1.35 | 0 | 1.4 | 0
4 x STÅLBJELKE | +0.993 | +0.872 | 95.5 | 73 | 0.036 | 26.512 | 0 | 1.35 | 0 | 1.4 | 0
STÅLBJELKE | +0.322 | +0.201 | 120.5 | 73 | 0.031 | 26.371 | 0 | 1.17 | 0 | 1.2 | 1.5708

# IfcBeam: Ø76.1*6.3 (12)
In: Undefined
Description: Ø76.1*6.3; Material: STEEL/S355J2H
Tekla Common - Class: 4; Phase: 9; Bottom elevation: +0.155
Tekla Quantity - Width: 76.1 mm; Height: 76.1 mm; Gross footprint area: 0.001 m2; Volume: 0 m3
BeamBaseQuantities - OuterSurfaceArea: 0 m2; NetVolume: 0 m3
Pset_BeamCommon - Slope: 1.5708 rad
Name | Top elevation | Tekla Quantity, Length (mm) = BeamBaseQuantities, Length (mm) | Net surface area (m2) | Area per tons (m2) | Weight (kg) | NetWeight (kg)
11 x STÅLBJELKE | +0.240 | 85 | 0.022 | 24.111 | 0.9 | 0.9
STÅLBJELKE | +0.197 | 42 | 0.011 | 25.784 | 0.44 | 0.3

# IfcColumn: EPD813*813*610*610*10 (2)
In: Undefined
Description: EPD813*813*610*610*10; Material: STEEL/Steel_Undefined
Tekla Common - Class: 3; Phase: 6; Top elevation: +2.500; Bottom elevation: +2.100
Tekla Quantity - Length: 400 mm; Width: 813 mm; Height: 813 mm; Net surface area: 0.943 m2; Area per tons: 13.246 m2; Gross footprint area: 0.019 m2; Volume: 0.009 m3; Weight: 71.16 kg
ColumnBaseQuantities - Length: 400 mm; OuterSurfaceArea: 0.8 m2; NetVolume: 0 m3; NetWeight: 71.2 kg
Pset_ColumnCommon - Slope: 1.5708 rad

# IfcColumn: Ø610*10 (2)
In: Undefined
Description: Ø610*10; Material: STEEL/Steel_Undefined
Tekla Common - Class: 3; Phase: 6; Top elevation: +6.260; Bottom elevation: +2.500
Tekla Quantity - Length: 3760 mm; Width: 610 mm; Height: 610 mm; Net surface area: 7.217 m2; Area per tons: 13.026 m2; Gross footprint area: 0.019 m2; Volume: 0.071 m3; Weight: 554.08 kg
ColumnBaseQuantities - Length: 3760 mm; OuterSurfaceArea: 7.2 m2; NetVolume: 0.1 m3; NetWeight: 554.1 kg
Pset_ColumnCommon - Slope: 1.5708 rad

# IfcColumn: Ø813*12.5 (4)
In: Undefined
Description: Ø813*12.5; Material: STEEL/Steel_Undefined
Tekla Common - Class: 3; Phase: 6
Tekla Quantity - Width: 813 mm; Height: 813 mm; Gross footprint area: 0.031 m2
Pset_ColumnCommon - Slope: 1.5708 rad
Name | Top elevation | Bottom elevation | Tekla Quantity, Length (mm) = ColumnBaseQuantities, Length (mm) | Net surface area (m2) | Area per tons (m2) | Volume (m3) | Weight (kg) | OuterSurfaceArea (m2) | NetVolume (m3) | NetWeight (kg)
2 x HEISTÅRN | +2.100 | -2.900 | 5000 | 12.793 | 10.398 | 0.157 | 1230.33 | 12.8 | 0.2 | 1230.3
2 x HEISTÅRN | -2.900 | -5.000 | 2100 | 5.392 | 10.434 | 0.066 | 516.74 | 5.4 | 0.1 | 516.7

# IfcFastener (189)
In: Undefined
Tekla Weld Common - Intermittent type: Continuous; Assembly type: Workshop; Weld number: 0; Electrode strength: 0; Electrode coefficent: 0
Tekla Weld Above Line - Effective throat1: 0 mm; Weld angle1: 0; Root opening1: 0 mm; Root face thickness1: 0 mm; Length1: 0 mm; Pitch1: 0; Increment count1: 0
Tekla Weld Below Line - Effective throat2: 0 mm; Weld angle2: 0; Root opening2: 0 mm; Root face thicness2: 0 mm; Length2: 0 mm; Pitch2: 0; Increment count2: 0
Name | Edge/Around | Length (mm) | Volume (m3) | Type1 | Size1 (mm) | Cross section area1 (m2) | Actual length1 (mm) | Size2 (mm) | Cross section area2 (m2) | Actual length2 (mm)
2 x Weld | Around | 325 | 0 | W10 | 10 | 0.0001 | 325 | 0 | 0 | 0 | Tekla Weld Below Line - Type2: W10
Weld | Around | 830 | 0 | W10 | 10 | 0.0001 | 830 | 0 | 0 | 0 | Tekla Weld Below Line - Type2: W10
4 x Weld | Around | 205 | 0 | W10 | 6 | 0.00004 | 205 | 0 | 0 | 0
2 x Weld | Around | 539 | 0 | W10 | 6 | 0.00004 | 539 | 0 | 0 | 0 | Tekla Weld Below Line - Type2: W10
2 x Weld | Around | 611.1 | 0 | W10 | 6 | 0.00004 | 611.1 | 0 | 0 | 0 | Tekla Weld Below Line - Type2: W10
Weld | Around | 535.9 | 0 | W10 | 6 | 0.00004 | 535.9 | 0 | 0 | 0 | Tekla Weld Below Line - Type2: W10
Weld | Around | 617.6 | 0 | W10 | 6 | 0.00004 | 617.6 | 0 | 0 | 0 | Tekla Weld Below Line - Type2: W10
Weld | Around | 626.6 | 0 | W10 | 6 | 0.00004 | 626.6 | 0 | 0 | 0 | Tekla Weld Below Line - Type2: W10
Weld | Around | 207 | 0 | W10 | 6 | 0 | 207 | 0 | 0 | 0 | Tekla Weld Below Line - Type2: W10
Weld | Around | 213 | 0 | W10 | 6 | 0 | 213 | 0 | 0 | 0 | Tekla Weld Below Line - Type2: W10
Weld | Around | 629.7 | 0 | W10 | 6 | 0.00004 | 629.7 | 0 | 0 | 0 | Tekla Weld Below Line - Type2: W10
4 x Weld | Around | 82.5 | 0 | W10 | 8 | 0.00004 | 82.5 | 5 | 0 | 0
4 x Weld | Around | 82.5 | 0 | W10 | 8 | 0.00002 | 82.5 | 5 | 0 | 0
10 x Weld | Around | 82.5 | 0 | W10 | 6 | 0.00001 | 82.5 | 6 | 0 | 0
2 x Weld | Around | 631.7 | 0 | W10 | 6 | 0.00004 | 631.7 | 0 | 0 | 0 | Tekla Weld Below Line - Type2: W10
2 x Weld | Around | 515 | 0 | W10 | 6 | 0.00004 | 515 | 0 | 0 | 0 | Tekla Weld Below Line - Type2: W10
2 x Weld | Around | 617.2 | 0 | W10 | 6 | 0.00004 | 617.2 | 0 | 0 | 0 | Tekla Weld Below Line - Type2: W10
Weld | Around | 612 | 0 | W10 | 6 | 0.00004 | 612 | 0 | 0 | 0 | Tekla Weld Below Line - Type2: W10
2 x Weld | Around | 621.9 | 0 | W10 | 6 | 0.00004 | 621.9 | 0 | 0 | 0 | Tekla Weld Below Line - Type2: W10
Weld | Around | 527 | 0 | W10 | 6 | 0.00004 | 527 | 0 | 0 | 0 | Tekla Weld Below Line - Type2: W10
Weld | Around | 528 | 0 | W10 | 6 | 0.00004 | 528 | 0 | 0 | 0 | Tekla Weld Below Line - Type2: W10
Weld | Around | 438.2 | 0 | W10 | 6 | 0.00004 | 438.2 | 0 | 0 | 0 | Tekla Weld Below Line - Type2: W10
Weld | Around | 673.5 | 0 | W10 | 6 | 0.00004 | 673.5 | 0 | 0 | 0 | Tekla Weld Below Line - Type2: W10
2 x Weld | Around | 82.5 | 0 | W10 | 6 | 0.00002 | 82.5 | 6 | 0 | 0
Weld | Around | 605.7 | 0 | W10 | 6 | 0.00004 | 605.7 | 0 | 0 | 0 | Tekla Weld Below Line - Type2: W10
Weld | Around | 385 | 0 | W10 | 6 | 0.00004 | 385 | 0 | 0 | 0 | Tekla Weld Below Line - Type2: W10
Weld | Around | 289 | 0 | W10 | 6 | 0.00004 | 289 | 0 | 0 | 0 | Tekla Weld Below Line - Type2: W10
Weld | Around | 536.1 | 0 | W10 | 6 | 0.00004 | 536.1 | 6 | 0 | 0
Weld | Around | 617.6 | 0 | W10 | 6 | 0.00004 | 617.6 | 6 | 0 | 0
2 x Weld | Around | 82.5 | 0 | W10 | 8 | 0.00002 | 82.5 | 0 | 0 | 0
Weld | Around | 207 | 0 | W10 | 6 | 0 | 207 | 0 | 0 | 0
Weld | Around | 626.4 | 0 | W10 | 6 | 0.00004 | 626.4 | 0 | 0 | 0
2 x Weld | Around | 82.5 | 0 | W10 | 8 | 0.00004 | 82.5 | 0 | 0 | 0
2 x Weld | Around | 2160.7 | 0 | W10 | 6 | 0.00004 | 2160.7 | 0 | 0 | 0
3 x Weld | Around | 2175.7 | 0 | W10 | 6 | 0.00004 | 2175.7 | 0 | 0 | 0
6 x Weld | Around | 120 | 0 | W10 | 20 | 0.0002 | 120 | 0 | 0 | 0
6 x Weld | Edge | 300 | 0 | W10 | 20 | 0.00014 | 300 | 0 | 0 | 0
2 x Weld | Around | 300.1 | 0 | W10 | 5 | 0.00002 | 300.1 | 0 | 0 | 0
2 x Weld | Around | 300 | 0 | W10 | 5 | 0.00004 | 300 | 0 | 0 | 0
4 x Weld | Edge | 300 | 0 | W10 | 10 | 0.0001 | 300 | 10 | 0.0001 | 300 | Tekla Weld Below Line - Type2: W10
2 x Weld | Edge | 300 | 0 | W10 | 25 | 0.00024 | 300 | 0 | 0 | 0
2 x Weld | Edge | 300 | 0 | W10 | 20 | 0.0001 | 300 | 0 | 0 | 0
2 x Weld | Edge | 300 | 0 | W10 | 35 | 0.00045 | 300 | 0 | 0 | 0
Weld | Edge | 8700 | 0.001 |  | 10 | 0.00007 | 0 | 20 | 0.0004 | 8700 | Tekla Weld Below Line - Type2: W10
2 x Weld | Edge | 597 | 0 | W10 | 20 | 0.0002 | 597 | 0 | 0 | 0
2 x Weld | Edge | 300 | 0 | W10 | 40 | 0.00045 | 300 | 0 | 0 | 0
2 x Weld | Edge | 300 | 0 | W10 | 15 | 0.0004 | 300 | 15 | 0 | 0 | Tekla Weld Below Line - Type2: W10
2 x Weld | Edge | 300 | 0 | W10 | 30 | 0.00022 | 300 | 0 | 0 | 0
2 x Weld | Edge | 300 | 0 | W10 | 20 | 0.0002 | 300 | 0 | 0 | 0
9 x Weld | Around | 666.2 | 0 | W10 | 5 | 0 | 666.2 | 0 | 0 | 0
2 x Weld | Around | 300 | 0 | W10 | 6 | 0.00022 | 300 | 0 | 0 | 0
Weld | Edge | 300 | 0 |  | 0 | 0.00048 | 0 | 20 | 0.00067 | 300 | Tekla Weld Below Line - Type2: W10
2 x Weld | Around | 453 | 0 |  | 0 | 0.00014 | 0 | 20 | 0.00109 | 453 | Tekla Weld Below Line - Type2: W10
2 x Weld | Edge | 874.6 | 0 | W10 | 5 | 0.00004 | 874.6 | 0 | 0 | 0
2 x Weld | Edge | 749.3 | 0 | W10 | 5 | 0 | 749.3 | 0 | 0 | 0
Weld | Around | 9000 | 0.005 | W10 | 35 | 0.00058 | 9000 | 35 | 0 | 0 | Tekla Weld Below Line - Type2: W10
2 x Weld | Around | 300 | 0 | W10 | 20 | 0.0002 | 300 | 0 | 0 | 0
2 x Weld | Around | 300 | 0 | W10 | 10 | 0.00007 | 300 | 10 | 0 | 0 | Tekla Weld Below Line - Type2: W10
2 x Weld | Around | 300 | 0 | W10 | 10 | 0.00012 | 300 | 10 | 0 | 0 | Tekla Weld Below Line - Type2: W10
2 x Weld | Around | 300 | 0 |  | 0 | 0.0002 | 0 | 20 | 0.00068 | 300 | Tekla Weld Below Line - Type2: W10
Weld | Edge | 300 | 0 |  | 0 | 0.00048 | 0 | 30 | 0.0015 | 300 | Tekla Weld Below Line - Type2: W10
24 x Weld | Around | 1063 | 0 | W10 | 5 | 0.00004 | 1063 | 0 | 0 | 0
4 x Weld | Around | 425 | 0 | W10 | 10 | 0.0001 | 425 | 0 | 0 | 0
Weld | Around | 180 | 0 | W10 | 5 | 0.00001 | 180 | 5 | 0 | 0
8 x Weld | Around | 180 | 0 | W10 | 6 | 0.00002 | 180 | 0 | 0 | 0
Weld | Around | 180 | 0 | W10 | 6 | 0.00001 | 180 | 5 | 0 | 0
Weld | Around | 62.5 | 0 | W10 | 6 | 0.00001 | 62.5 | 5 | 0 | 0
Weld | Around | 180 | 0 | W10 | 8 | 0.00002 | 180 | 0 | 0 | 0
Weld | Around | 301.3 | 0 | W10 | 5 | 0.00004 | 301.3 | 5 | 0.00003 | 301.3 | Tekla Weld Below Line - Type2: W10
Weld | Around | 180 | 0 | W10 | 8 | 0.00004 | 180 | 0 | 0 | 0
4 x Weld | Around | 180 | 0 | W10 | 5 | 0.0001 | 180 | 0 | 0 | 0
2 x Weld | Around | 180 | 0 | W10 | 8 | 0.00002 | 180 | 5 | 0 | 0
2 x Weld | Around | 180 | 0 | W10 | 8 | 0.00004 | 180 | 5 | 0 | 0
4 x Weld | Around | 180 | 0 | W10 | 5 | 0.0001 | 180 | 5 | 0 | 0
2 x Weld | Around | 180 | 0 | W10 | 6 | 0.00001 | 180 | 0 | 0 | 0
2 x Weld | Around | 1182 | 0 | W10 | 5 | 0.00004 | 1182 | 0 | 0 | 0

# IfcMechanicalFastener: Bolt assembly (1241)
In: Undefined
Material: 8
Tekla Bolt - Bolt Name: 6K; Location: Site; Slotted hole x: 0 mm
Name | NominalDiameter (mm) = Washer diameter (mm) | NominalLength (mm) | Bolt standard | Bolt length (mm) | Bolt size (mm) | Bolt count | Bolt hole diameter (mm) | Slotted hole y (mm) | Nut name | Nut type | Nut count | Washer name | Washer type | Washer count
6 x Bolt assembly | 12 | 40 | NS-ISO4014 | 40 | 12 | 2 | 13 | 0 | 6K-mutter M12-NS-ISO 4032 | 4032 | 2 | Underlagsskive M12-NS-ISO 7089 | 7089 | 4
26 x Bolt assembly | 12 | 100 | NS-ISO4014 | 100 | 12 | 2 | 14 | 0 | 6K-mutter M12-NS-ISO 4032 | 4032 | 4 | Underlagsskive M12-NS-ISO 7089 | 7089 | 4
206 x Bolt assembly | 20 | 140 | NS-ISO4017 | 140 | 20 | 2 | 20 | 0 | 6K-mutter M20-NS-ISO 4032 | 4032 | 2 | Underlagsskive M20-NS-ISO 7089 | 7089 | 4
Bolt assembly | 20 | 150 | NS-ISO4017 | 150 | 20 | 2 | 20 | 0 | 6K-mutter M20-NS-ISO 4032 | 4032 | 2 | Underlagsskive M20-NS-ISO 7089 | 7089 | 4
2 x Bolt assembly | 16 | 90 | NS-ISO4017 | 90 | 16 | 8 | 18 | 0 | 6K-mutter M16-NS-ISO 4032 | 4032 | 8 | Underlagsskive M16-NS-ISO 7089 | 7089 | 8
96 x Bolt assembly | 20 | 15 | DIN 7990 | 15 | 22 | 6 | 22 | 0 | 6K-mutter 20-DIN 555 | 555 | 0 | Underlagsskive M20-NS-ISO 7089 | 7089 | 0
4 x Bolt assembly | 24 | 70 | NS-ISO4014 | 70 | 24 | 3 | 26 | 0 | 6K-mutter M24-NS-ISO 4032 | 4032 | 3 | Underlagsskive M24-NS-ISO 7089 | 7089 | 6
2 x Bolt assembly | 24 | 70 | NS-ISO4014 | 70 | 24 | 7 | 26 | 0 | 6K-mutter M24-NS-ISO 4032 | 4032 | 7 | Underlagsskive M24-NS-ISO 7089 | 7089 | 14
4 x Bolt assembly | 24 | 100 | NS-ISO4014 | 100 | 24 | 2 | 26 | 0 | 6K-mutter M24-NS-ISO 4032 | 4032 | 2 | Underlagsskive M24-NS-ISO 7089 | 7089 | 4
4 x Bolt assembly | 12 | 40 | NS-ISO4014 | 40 | 12 | 1 | 12 | 0 | 6K-mutter M12-NS-ISO 4032 | 4032 | 1 | Underlagsskive M12-NS-ISO 7089 | 7089 | 1
4 x Bolt assembly | 24 | 80 | NS-ISO4014 | 80 | 24 | 3 | 26 | 0 | 6K-mutter M24-NS-ISO 4032 | 4032 | 3 | Underlagsskive M24-NS-ISO 7089 | 7089 | 6
2 x Bolt assembly | 24 | 80 | NS-ISO4014 | 80 | 24 | 7 | 26 | 0 | 6K-mutter M24-NS-ISO 4032 | 4032 | 7 | Underlagsskive M24-NS-ISO 7089 | 7089 | 14
2 x Bolt assembly | 24 | 80 | NS-ISO4014 | 80 | 24 | 4 | 26 | 0 | 6K-mutter M24-NS-ISO 4032 | 4032 | 4 | Underlagsskive M24-NS-ISO 7089 | 7089 | 8
4 x Bolt assembly | 24 | 500 | NS-ISO4014 | 500 | 24 | 3 | 26 | 0 | 6K-mutter M24-NS-ISO 4032 | 4032 | 3 | Underlagsskive M24-NS-ISO 7089 | 7089 | 6
2 x Bolt assembly | 24 | 500 | NS-ISO4014 | 500 | 24 | 7 | 26 | 0 | 6K-mutter M24-NS-ISO 4032 | 4032 | 7 | Underlagsskive M24-NS-ISO 7089 | 7089 | 14
414 x Bolt assembly | 20 | 15 | NS-ISO4014 | 15 | 22 | 1 | 22 | 0 | 6K-mutter M20-NS-ISO 4032 | 4032 | 0 | Underlagsskive M20-NS-ISO 7089 | 7089 | 0
16 x Bolt assembly | 20 | 180 | NS-ISO4014 | 180 | 20 | 4 | 22 | 33 | 6K-mutter M20-NS-ISO 4032 | 4032 | 4 | Underlagsskive M20-NS-ISO 7089 | 7089 | 8
4 x Bolt assembly | 30 | 100 | NS-ISO4014 | 100 | 30 | 4 | 30.2 | 0 | 6K-mutter M30-NS-ISO 4032 | 4032 | 4 | Underlagsskive M30-NS-ISO 7089 | 7089 | 8
20 x Bolt assembly | 16 | 10.0001 | NS-ISO4014 | 10 | 18 | 1 | 18 | 0 | 6K-mutter M16-NS-ISO 4032 | 4032 | 0 | Underlagsskive M16-NS-ISO 7089 | 7089 | 0
8 x Bolt assembly | 30 | 30 | NS-ISO4014 | 30 | 32 | 4 | 32 | 0 | 6K-mutter M30-NS-ISO 4032 | 4032 | 0 | Underlagsskive M30-NS-ISO 7089 | 7089 | 0
12 x Bolt assembly | 12 | 100 | NS-ISO4014 | 100 | 12 | 1 | 13 | 0 | 6K-mutter M12-NS-ISO 4032 | 4032 | 1 | Underlagsskive M12-NS-ISO 7089 | 7089 | 2
34 x Bolt assembly | 20 | 60 | NS-ISO4014 | 60 | 20 | 4 | 22 | 0 | 6K-mutter M20-NS-ISO 4032 | 4032 | 4 | Underlagsskive M20-NS-ISO 7089 | 7089 | 8
2 x Bolt assembly | 16 | 100 | DIN 7990 | 100 | 16 | 1 | 16 | 0 | 6K-mutter 16-DIN 555 | 555 | 0 | Underlagsskive M16-NS-ISO 7089 | 7089 | 0
2 x Bolt assembly | 12 | 90 | DIN 7990 | 90 | 12 | 1 | 14 | 0 | 6K-mutter 12-DIN 555 | 555 | 1 | Underlagsskive M12-NS-ISO 7089 | 7089 | 1
2 x Bolt assembly | 20 | 90 | DIN 7990 | 90 | 20 | 20 | 22 | 0 | 6K-mutter 20-DIN 555 | 555 | 20 | Underlagsskive M20-NS-ISO 7089 | 7089 | 20
96 x Bolt assembly | 8 | 30 | NS-ISO4014 | 30 | 8 | 1 | 10 | 0 | 6K-mutter M8-NS-ISO 4032 | 4032 | 1 | Underlagsskive M8-NS-ISO 7089 | 7089 | 2
34 x Bolt assembly | 20 | 75 | NS-ISO4014 | 75 | 20 | 4 | 22 | 0 | 6K-mutter M20-NS-ISO 4032 | 4032 | 4 | Underlagsskive M20-NS-ISO 7089 | 7089 | 8
80 x Bolt assembly | 12 | 80 | DIN 931 | 80 | 12 | 1 | 13 | 0 | 6K-mutter M12-DIN 934 | 934 | 1 | Underlagsskive M12-DIN 125A | 125A | 1
4 x Bolt assembly | 24 | 100 | NS-ISO4014 | 100 | 24 | 4 | 26 | 0 | 6K-mutter M24-NS-ISO 4032 | 4032 | 0 | Underlagsskive M24-NS-ISO 7089 | 7089 | 4
6 x Bolt assembly | 16 | 50 | NS-ISO4014 | 50 | 16 | 3 | 18 | 0 | 6K-mutter M16-NS-ISO 4032 | 4032 | 3 | Underlagsskive M16-NS-ISO 7089 | 7089 | 6
40 x Bolt assembly | 12 | 180 | DIN 931 | 180 | 12 | 1 | 13 | 0 | 6K-mutter M12-DIN 934 | 934 | 1 | Underlagsskive M12-DIN 125A | 125A | 1
40 x Bolt assembly | 12 | 180 | DIN 931 | 180 | 12 | 1 | 13 | 0 | 6K-mutter M12-DIN 934 | 934 | 1 | Underlagsskive M12-DIN 125A | 125A | 2
2 x Bolt assembly | 24 | 550 | NS-ISO4014 | 550 | 24 | 4 | 26 | 0 | 6K-mutter M24-NS-ISO 4032 | 4032 | 0 | Underlagsskive M24-NS-ISO 7089 | 7089 | 4
4 x Bolt assembly | 24 | 120 | NS-ISO4014 | 120 | 24 | 4 | 26 | 0 | 6K-mutter M24-NS-ISO 4032 | 4032 | 4 | Underlagsskive M24-NS-ISO 7089 | 7089 | 8
6 x Bolt assembly | 24 | 120 | NS-ISO4014 | 120 | 24 | 1 | 26 | 0 | 6K-mutter M24-NS-ISO 4032 | 4032 | 1 | Underlagsskive M24-NS-ISO 7089 | 7089 | 2
2 x Bolt assembly | 36 | 180 | NS-ISO4014 | 180 | 36 | 2 | 39 | 0 | 6K-mutter M36-NS-ISO 4032 | 4032 | 2 | Underlagsskive M36-NS-ISO 7089 | 7089 | 4
2 x Bolt assembly | 36 | 280 | NS-ISO4014 | 280 | 36 | 12 | 39 | 0 | 6K-mutter M36-NS-ISO 4032 | 4032 | 12 | Underlagsskive M36-NS-ISO 7089 | 7089 | 24
2 x Bolt assembly | 36 | 280 | NS-ISO4014 | 280 | 36 | 16 | 39 | 0 | 6K-mutter M36-NS-ISO 4032 | 4032 | 16 | Underlagsskive M36-NS-ISO 7089 | 7089 | 32
4 x Bolt assembly | 24 | 90 | NS-ISO4014 | 90 | 24 | 4 | 26 | 0 | 6K-mutter M24-NS-ISO 4032 | 4032 | 4 | Underlagsskive M24-NS-ISO 7089 | 7089 | 8
18 x Bolt assembly | 16 | 65 | NS-ISO4014 | 65 | 16 | 2 | 18 | 0 | 6K-mutter M16-NS-ISO 4032 | 4032 | 2 | Underlagsskive M16-NS-ISO 7089 | 7089 | 4
20 x Bolt assembly | 16 | 70 | NS-ISO4014 | 70 | 16 | 1 | 18 | 0 | 6K-mutter M16-NS-ISO 4032 | 4032 | 1 | Underlagsskive M16-NS-ISO 7089 | 7089 | 2
2 x Bolt assembly | 16 | 65 | NS-ISO4014 | 65 | 16 | 4 | 18 | 0 | 6K-mutter M16-NS-ISO 4032 | 4032 | 4 | Underlagsskive M16-NS-ISO 7089 | 7089 | 8

# IfcPlate: 150*300 (4)
In: Undefined
Description: 150*300; Material: MISCELLANEOUS/NULLVEKT
Tekla Common - Class: 6; Phase: 100
Tekla Quantity - Width: 150 mm; Height: 300 mm; Area per tons: 0 m2; Gross footprint area: 0 m2; Weight: 0 kg
PlateBaseQuantities - Width: 300 mm; GrossArea: 0.2 m2; CrossSectionArea: 0 m2; NetVolume: 0 m3; GrossVolume: 0 m3
Name | Top elevation | Bottom elevation | Length (mm) | Net surface area (m2) | Volume (m3) | NetArea (m2)
2 x PLATE | -0.185 | -0.875 | 690.2 | 0.711 | 0.031 | 0.6
2 x PLATE | -0.035 | -0.865 | 830.2 | 0.837 | 0.037 | 0.8

# IfcPlate: PL10*100 (6)
In: Undefined
Description: PL10*100; Material: STEEL/S355N
Tekla Common - Class: 4; Phase: 10; Top elevation: -0.130; Bottom elevation: -0.230
Tekla Quantity - Length: 130 mm; Width: 10 mm; Height: 100 mm; Net surface area: 0.031 m2; Area per tons: 29.985 m2; Gross footprint area: 0.001 m2; Volume: 0 m3; Weight: 1.02 kg
PlateBaseQuantities - Width: 100 mm; NetArea: 0 m2; GrossArea: 0 m2; CrossSectionArea: 0 m2; NetVolume: 0 m3; GrossVolume: 0 m3

# IfcPlate: PL10*110 (2)
In: Undefined
Description: PL10*110; Material: STEEL/S355N
Tekla Common - Class: 5; Phase: 13; Top elevation: -0.360; Bottom elevation: -0.530
Tekla Quantity - Length: 170 mm; Width: 10 mm; Height: 110 mm; Net surface area: 0.043 m2; Area per tons: 29.293 m2; Gross footprint area: 0.001 m2; Volume: 0 m3; Weight: 1.47 kg
PlateBaseQuantities - Width: 110 mm; NetArea: 0 m2; GrossArea: 0 m2; CrossSectionArea: 0 m2; NetVolume: 0 m3; GrossVolume: 0 m3

# IfcPlate: PL10*120 (20)
In: Undefined
Description: PL10*120; Material: STEEL/S355J2
Tekla Common - Class: 11; Phase: 8; Top elevation: -0.845; Bottom elevation: -0.855
Tekla Quantity - Length: 220 mm; Width: 10 mm; Height: 120 mm; Net surface area: 0.059 m2; Area per tons: 28.759 m2; Gross footprint area: 0.027 m2; Volume: 0 m3; Weight: 2.07 kg
PlateBaseQuantities - Width: 120 mm; NetArea: 0.1 m2; GrossArea: 0 m2; CrossSectionArea: 0 m2; NetVolume: 0 m3; GrossVolume: 0 m3

# IfcPlate: PL10*135 (8)
In: Undefined
Description: PL10*135; Material: STEEL/S355N
Tekla Common - Class: 5; Phase: 13; Top elevation: -0.915; Bottom elevation: -1.165
Tekla Quantity - Length: 250 mm; Width: 10 mm; Height: 135 mm; Net surface area: 0.051 m2; Area per tons: 29.392 m2; Gross footprint area: 0.001 m2; Volume: 0 m3; Weight: 1.73 kg
PlateBaseQuantities - Width: 135 mm; NetArea: 0.1 m2; GrossArea: 0 m2; CrossSectionArea: 0 m2; NetVolume: 0 m3; GrossVolume: 0 m3

# IfcPlate: PL10*170 (2)
In: Undefined
Description: PL10*170; Material: STEEL/S355N
Tekla Common - Class: 5; Phase: 13; Top elevation: -0.360; Bottom elevation: -0.530
Tekla Quantity - Length: 175 mm; Width: 10 mm; Height: 170 mm; Net surface area: 0.066 m2; Area per tons: 28.432 m2; Gross footprint area: 0.002 m2; Volume: 0 m3; Weight: 2.34 kg
PlateBaseQuantities - Width: 170 mm; NetArea: 0.1 m2; GrossArea: 0 m2; CrossSectionArea: 0 m2; NetVolume: 0 m3; GrossVolume: 0 m3

# IfcPlate: PL10*197 (2)
In: Undefined
Description: PL10*197; Material: STEEL/Steel_Undefined
Tekla Common - Class: 3; Phase: 6; Top elevation: +2.199; Bottom elevation: +2.009
Tekla Quantity - Length: 248.4 mm; Width: 10 mm; Height: 196.8 mm; Net surface area: 0.066 m2; Area per tons: 28.813 m2; Gross footprint area: 0 m2; Volume: 0 m3; Weight: 2.3 kg
PlateBaseQuantities - Width: 196.8 mm; NetArea: 0.1 m2; GrossArea: 0 m2; CrossSectionArea: 0 m2; NetVolume: 0 m3; GrossVolume: 0 m3

# IfcPlate: PL10*230 (20)
In: Undefined
Description: PL10*230; Material: STEEL/S355J2
Tekla Common - Class: 11; Phase: 8; Top elevation: +0.010; Bottom elevation: -0.000
Tekla Quantity - Width: 10 mm; Height: 230 mm; Volume: 0.001 m3
PlateBaseQuantities - Width: 230 mm; GrossArea: 0.1 m2; CrossSectionArea: 0 m2; NetVolume: 0 m3; GrossVolume: 0 m3
Name | Length (mm) | Net surface area (m2) | Area per tons (m2) | Gross footprint area (m2) | Weight (kg) | NetArea (m2)
18 x PLATE | 360 | 0.141 | 27.848 | 0.064 | 5.05 | 0.1
2 x PLATE | 560 | 0.219 | 27.45 | 0.102 | 8.01 | 0.2

# IfcPlate: PL10*250 (2)
In: Undefined
Description: PL10*250; Material: STEEL/S355N
Tekla Common - Class: 4; Phase: 10; Top elevation: -0.005; Bottom elevation: -0.255
Tekla Quantity - Length: 280 mm; Width: 10 mm; Height: 250 mm; Net surface area: 0.151 m2; Area per tons: 27.407 m2; Gross footprint area: 0.003 m2; Volume: 0.001 m3; Weight: 5.5 kg
PlateBaseQuantities - Width: 250 mm; NetArea: 0.2 m2; GrossArea: 0.1 m2; CrossSectionArea: 0 m2; NetVolume: 0 m3; GrossVolume: 0 m3

# IfcPlate: PL10*90 (10)
In: Undefined
Description: PL10*90; Material: STEEL/S355N
Tekla Common - Class: 4; Phase: 10
Tekla Quantity - Length: 280 mm; Width: 10 mm; Height: 90 mm; Net surface area: 0.058 m2; Area per tons: 29.218 m2; Gross footprint area: 0.003 m2; Volume: 0 m3; Weight: 1.98 kg
PlateBaseQuantities - Width: 90 mm; NetArea: 0.1 m2; GrossArea: 0 m2; CrossSectionArea: 0 m2; NetVolume: 0 m3; GrossVolume: 0 m3
Name | Top elevation | Bottom elevation
8 x PLATE | -0.175 | -0.265
2 x PLATE | -0.005 | -0.095

# IfcPlate: PL120*30 (6)
In: Undefined
Description: PL120*30; Material: STEEL/S355N (Z-25)
Tekla Common - Class: 4; Phase: 11; Top elevation: +0.005; Bottom elevation: -0.025
Tekla Quantity - Length: 60 mm; Width: 120 mm; Height: 30 mm; Net surface area: 0.025 m2; Area per tons: 14.633 m2; Gross footprint area: 0.006 m2; Volume: 0 m3; Weight: 1.68 kg
PlateBaseQuantities - Width: 30 mm; NetArea: 0 m2; GrossArea: 0 m2; CrossSectionArea: 0 m2; NetVolume: 0 m3; GrossVolume: 0 m3

# IfcPlate: PL120*545 (9)
In: Undefined
Description: PL120*545; Material: STEEL/Steel_Undefined
Tekla Common - Class: 5; Phase: 15; Top elevation: +0.000; Bottom elevation: -0.120
Tekla Quantity - Length: 888 mm; Width: 120 mm; Height: 545 mm; Net surface area: 1.312 m2; Area per tons: 2.878 m2; Gross footprint area: 0.484 m2; Volume: 0.058 m3; Weight: 455.89 kg
PlateBaseQuantities - Width: 545 mm; NetArea: 1.3 m2; GrossArea: 0.5 m2; CrossSectionArea: 0 m2; NetVolume: 0.1 m3; GrossVolume: 0.1 m3

# IfcPlate: PL120*888 (63)
In: Undefined
Description: PL120*888; Material: STEEL/Steel_Undefined
Tekla Common - Class: 5; Phase: 15; Top elevation: +0.000; Bottom elevation: -0.120
Tekla Quantity - Width: 120 mm; Height: 888 mm; Area per tons: 2.519 m2
PlateBaseQuantities - Width: 888 mm; NetArea: 4.9 m2; CrossSectionArea: 0 m2; NetVolume: 0.2 m3; GrossVolume: 0.2 m3
Name | Length (mm) | Net surface area (m2) | Gross footprint area (m2) | Volume (m3) | Weight (kg) | GrossArea (m2)
54 x PLATE | 2330 | 4.91 | 2.069 | 0.248 | 1949.03 | 2.1
9 x PLATE | 2308 | 4.866 | 2.049 | 0.246 | 1930.62 | 2

# IfcPlate: PL15*110 (4)
In: Undefined
Description: PL15*110; Material: STEEL/S355N
Tekla Common - Class: 5; Phase: 13
Tekla Quantity - Length: 597 mm; Width: 15 mm; Height: 110 mm; Net surface area: 0.12 m2; Area per tons: 20.198 m2; Gross footprint area: 0.051 m2; Volume: 0.001 m3; Weight: 5.96 kg
PlateBaseQuantities - Width: 110 mm; NetArea: 0.1 m2; GrossArea: 0.1 m2; CrossSectionArea: 0 m2; NetVolume: 0 m3; GrossVolume: 0 m3
Name | Top elevation | Bottom elevation
2 x PLATE | -0.530 | -0.545
2 x PLATE | -0.345 | -0.360

# IfcPlate: PL15*122 (2)
In: Undefined
Description: PL15*122; Material: STEEL/S355N
Tekla Common - Class: 4; Phase: 5; Top elevation: -0.438; Bottom elevation: -0.453
Tekla Quantity - Length: 267 mm; Width: 15 mm; Height: 122 mm; Net surface area: 0.077 m2; Area per tons: 20.028 m2; Gross footprint area: 0.033 m2; Volume: 0 m3; Weight: 3.84 kg
PlateBaseQuantities - Width: 122 mm; NetArea: 0.1 m2; GrossArea: 0 m2; CrossSectionArea: 0 m2; NetVolume: 0 m3; GrossVolume: 0 m3

# IfcPlate: PL15*132 (12)
In: Undefined
Description: PL15*132; Material: STEEL/S355N
Tekla Common - Phase: 5
Tekla Quantity - Width: 15 mm; Height: 132 mm; Volume: 0 m3
PlateBaseQuantities - Width: 132 mm; NetArea: 0.1 m2; GrossArea: 0 m2; CrossSectionArea: 0 m2; NetVolume: 0 m3; GrossVolume: 0 m3
Name | Class | Top elevation | Bottom elevation | Length (mm) | Net surface area (m2) | Area per tons (m2) | Gross footprint area (m2) | Weight (kg)
2 x PLATE | 130 | -0.438 | -0.453 | 180 | 0.057 | 20.331 | 0.024 | 2.8
2 x PLATE | 130 | -0.438 | -0.453 | 239 | 0.073 | 19.995 | 0.031 | 3.63
8 x PLATE | 4 | -0.610 | -0.860 | 250 | 0.053 | 20.949 | 0 | 2.54

# IfcPlate: PL15*137 (2)
In: Undefined
Description: PL15*137; Material: STEEL/S355N
Tekla Common - Class: 4; Phase: 5; Top elevation: -0.438; Bottom elevation: -0.453
Tekla Quantity - Length: 185 mm; Width: 15 mm; Height: 137 mm; Net surface area: 0.04 m2; Area per tons: 21.566 m2; Gross footprint area: 0.016 m2; Volume: 0 m3; Weight: 1.85 kg
PlateBaseQuantities - Width: 137 mm; NetArea: 0 m2; GrossArea: 0 m2; CrossSectionArea: 0 m2; NetVolume: 0 m3; GrossVolume: 0 m3

# IfcPlate: PL15*142 (4)
In: Undefined
Description: PL15*142; Material: STEEL/S355N
Tekla Common - Class: 4; Phase: 5; Top elevation: -0.438; Bottom elevation: -0.453
Tekla Quantity - Width: 15 mm; Height: 141.6 mm; Net surface area: 0.055 m2; Area per tons: 21.199 m2; Gross footprint area: 0.022 m2; Volume: 0 m3; Weight: 2.58 kg
PlateBaseQuantities - Width: 141.6 mm; NetArea: 0.1 m2; GrossArea: 0 m2; CrossSectionArea: 0 m2; NetVolume: 0 m3; GrossVolume: 0 m3
Name | Length (mm)
2 x PLATE | 298.1
2 x PLATE | 298

# IfcPlate: PL15*149 (4)
In: Undefined
Description: PL15*149; Material: STEEL/S355N
Tekla Common - Class: 4; Phase: 5; Top elevation: -0.438; Bottom elevation: -0.453
Tekla Quantity - Length: 301.3 mm; Width: 15 mm; Height: 148.9 mm; Net surface area: 0.058 m2; Gross footprint area: 0.023 m2; Volume: 0 m3; Weight: 2.76 kg
PlateBaseQuantities - Width: 148.9 mm; NetArea: 0.1 m2; GrossArea: 0 m2; CrossSectionArea: 0 m2; NetVolume: 0 m3; GrossVolume: 0 m3
Name | Area per tons (m2)
2 x PLATE | 20.996
2 x PLATE | 20.997

# IfcPlate: PL15*152 (4)
In: Undefined
Description: PL15*152; Material: STEEL/S355N
Tekla Common - Class: 4; Phase: 5; Top elevation: -0.438; Bottom elevation: -0.453
Tekla Quantity - Length: 303.4 mm; Width: 15 mm; Net surface area: 0.059 m2; Gross footprint area: 0.024 m2; Volume: 0 m3; Weight: 2.84 kg
PlateBaseQuantities - NetArea: 0.1 m2; GrossArea: 0 m2; CrossSectionArea: 0 m2; NetVolume: 0 m3; GrossVolume: 0 m3
Name | Height (mm) = Width (mm) | Area per tons (m2)
2 x PLATE | 152.3 | 20.915
2 x PLATE | 152 | 20.925

# IfcPlate: PL15*163 (4)
In: Undefined
Description: PL15*163; Material: STEEL/S355N
Tekla Common - Class: 4; Phase: 5; Top elevation: -0.438; Bottom elevation: -0.453
Tekla Quantity - Width: 15 mm; Height: 162.6 mm; Net surface area: 0.064 m2; Area per tons: 20.661 m2; Gross footprint area: 0.027 m2; Volume: 0 m3; Weight: 3.12 kg
PlateBaseQuantities - Width: 162.6 mm; NetArea: 0.1 m2; GrossArea: 0.1 m2; CrossSectionArea: 0 m2; NetVolume: 0 m3; GrossVolume: 0 m3
Name | Length (mm)
2 x PLATE | 308.4
2 x PLATE | 308.3

# IfcPlate: PL15*170 (2)
In: Undefined
Description: PL15*170; Material: STEEL/S355N
Tekla Common - Class: 4; Phase: 5; Top elevation: -0.438; Bottom elevation: -0.453
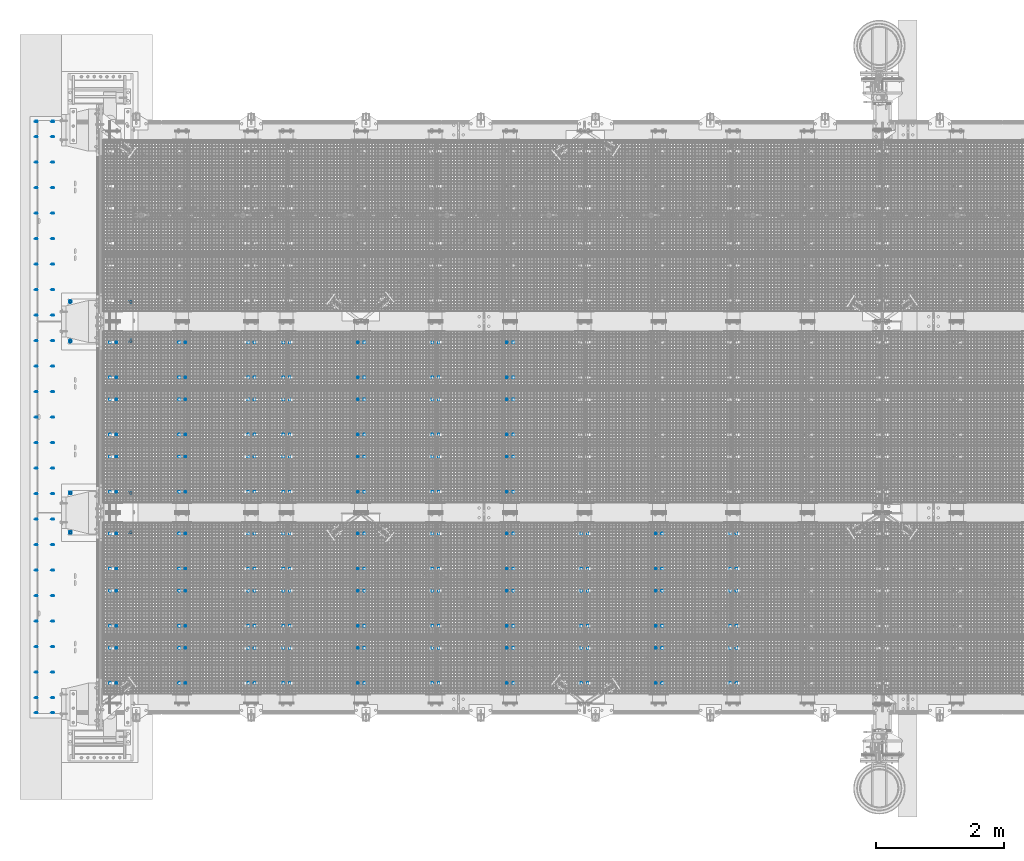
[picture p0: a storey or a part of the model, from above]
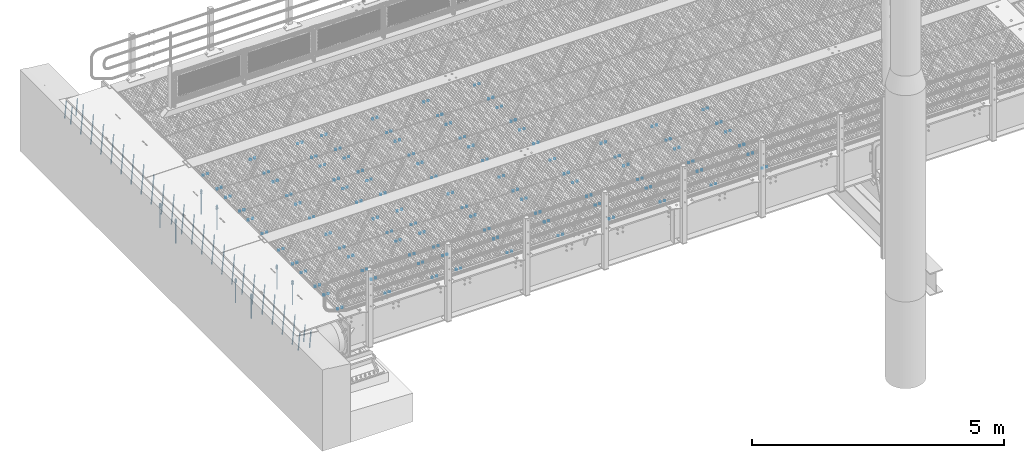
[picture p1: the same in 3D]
Properties of the parts of a building model (IFC2X3), part 2 of 2

# IfcPlate: PL15*170 (2)
Tekla Quantity - Length: 329.2 mm; Width: 15 mm; Height: 170.3 mm; Net surface area: 0.073 m2; Area per tons: 20.434 m2; Gross footprint area: 0.03 m2; Volume: 0 m3; Weight: 3.54 kg
PlateBaseQuantities - Width: 170.3 mm; NetArea: 0.1 m2; GrossArea: 0.1 m2; CrossSectionArea: 0 m2; NetVolume: 0 m3; GrossVolume: 0 m3

# IfcPlate: PL15*175 (4)
In: Undefined
Description: PL15*175; Material: STEEL/S355N (Z-25)
Tekla Common - Class: 5; Phase: 13
Tekla Quantity - Length: 605 mm; Width: 15 mm; Height: 175 mm; Net surface area: 0.235 m2; Area per tons: 18.862 m2; Gross footprint area: 0.106 m2; Volume: 0.002 m3; Weight: 12.47 kg
PlateBaseQuantities - Width: 175 mm; NetArea: 0.2 m2; GrossArea: 0.1 m2; CrossSectionArea: 0 m2; NetVolume: 0 m3; GrossVolume: 0 m3
Name | Top elevation | Bottom elevation
2 x PLATE | -0.345 | -0.360
2 x PLATE | -0.530 | -0.545

# IfcPlate: PL15*195 (32)
In: Undefined
Description: PL15*195; Material: STEEL/S355N
Tekla Common - Class: 4; Phase: 9
Tekla Quantity - Length: 260 mm; Width: 15 mm; Height: 195 mm; Net surface area: 0.114 m2; Area per tons: 19.2 m2; Gross footprint area: 0.05 m2; Volume: 0.001 m3; Weight: 5.93 kg
PlateBaseQuantities - Width: 195 mm; NetArea: 0.1 m2; GrossArea: 0.1 m2; CrossSectionArea: 0 m2; NetVolume: 0 m3; GrossVolume: 0 m3
Name | Top elevation | Bottom elevation
16 x PLATE | -0.120 | -0.135
16 x PLATE | +0.015 | +0.000

# IfcPlate: PL15*200 (26)
In: Undefined
Description: PL15*200; Material: STEEL/S355N (Z-25)
Tekla Common - Class: 14; Phase: 4; Top elevation: -0.345; Bottom elevation: -0.545
Tekla Quantity - Length: 200 mm; Width: 15 mm; Height: 200 mm; Net surface area: 0.092 m2; Area per tons: 19.533 m2; Gross footprint area: 0.003 m2; Volume: 0.001 m3; Weight: 4.71 kg
PlateBaseQuantities - Width: 200 mm; NetArea: 0.1 m2; GrossArea: 0 m2; CrossSectionArea: 0 m2; NetVolume: 0 m3; GrossVolume: 0 m3

# IfcPlate: PL15*220 (96)
In: Undefined
Description: PL15*220; Material: STEEL/S355N
Tekla Common - Class: 4; Phase: 2; Top elevation: -0.110; Bottom elevation: -0.330
Tekla Quantity - Length: 220 mm; Width: 15 mm; Height: 220 mm; Net surface area: 0.11 m2; Area per tons: 19.301 m2; Gross footprint area: 0.003 m2; Volume: 0.001 m3; Weight: 5.71 kg
PlateBaseQuantities - Width: 220 mm; NetArea: 0.1 m2; GrossArea: 0 m2; CrossSectionArea: 0 m2; NetVolume: 0 m3; GrossVolume: 0 m3

# IfcPlate: PL15*240 (4)
In: Undefined
Description: PL15*240; Material: STEEL/S355N
Tekla Common - Class: 5; Phase: 13; Top elevation: -0.325; Bottom elevation: -0.565
Tekla Quantity - Length: 240 mm; Width: 15 mm; Height: 240 mm; Net surface area: 0.13 m2; Area per tons: 19.108 m2; Gross footprint area: 0.004 m2; Volume: 0.001 m3; Weight: 6.78 kg
PlateBaseQuantities - Width: 240 mm; NetArea: 0.1 m2; GrossArea: 0.1 m2; CrossSectionArea: 0 m2; NetVolume: 0 m3; GrossVolume: 0 m3

# IfcPlate: PL15*250 (2)
In: Undefined
Description: PL15*250; Material: STEEL/S355N
Tekla Common - Class: 4; Phase: 5; Top elevation: -0.438; Bottom elevation: -0.453
Tekla Quantity - Length: 301 mm; Width: 15 mm; Height: 250 mm; Net surface area: 0.101 m2; Area per tons: 19.755 m2; Gross footprint area: 0.043 m2; Volume: 0.001 m3; Weight: 5.11 kg
PlateBaseQuantities - Width: 250 mm; NetArea: 0.1 m2; GrossArea: 0.1 m2; CrossSectionArea: 0 m2; NetVolume: 0 m3; GrossVolume: 0 m3

# IfcPlate: PL15*329 (2)
In: Undefined
Description: PL15*329; Material: STEEL/S355N
Tekla Common - Class: 4; Phase: 5; Top elevation: -0.438; Bottom elevation: -0.453
Tekla Quantity - Length: 401.9 mm; Width: 15 mm; Height: 329.1 mm; Net surface area: 0.146 m2; Area per tons: 19.333 m2; Gross footprint area: 0.064 m2; Volume: 0.001 m3; Weight: 7.55 kg
PlateBaseQuantities - Width: 329.1 mm; NetArea: 0.1 m2; GrossArea: 0.1 m2; CrossSectionArea: 0 m2; NetVolume: 0 m3; GrossVolume: 0 m3

# IfcPlate: PL15*333 (2)
In: Undefined
Description: PL15*333; Material: STEEL/S355N
Tekla Common - Class: 4; Phase: 5; Top elevation: -0.438; Bottom elevation: -0.453
Tekla Quantity - Length: 423.9 mm; Width: 15 mm; Height: 332.8 mm; Net surface area: 0.154 m2; Area per tons: 19.248 m2; Gross footprint area: 0.068 m2; Volume: 0.001 m3; Weight: 8.01 kg
PlateBaseQuantities - Width: 332.8 mm; NetArea: 0.2 m2; GrossArea: 0.1 m2; CrossSectionArea: 0 m2; NetVolume: 0 m3; GrossVolume: 0 m3

# IfcPlate: PL15*40 (3)
In: Undefined
Description: PL15*40; Material: STEEL/S355N
Tekla Common - Class: 130; Phase: 11; Top elevation: -0.030; Bottom elevation: -0.070
Tekla Quantity - Width: 15 mm; Height: 40 mm; Gross footprint area: 0.02 m2; Volume: 0.001 m3
PlateBaseQuantities - Width: 40 mm; NetArea: 0.3 m2; GrossArea: 0.1 m2; CrossSectionArea: 0 m2; NetVolume: 0 m3; GrossVolume: 0 m3
Name | Length (mm) | Net surface area (m2) | Area per tons (m2) | Weight (kg)
2 x PLATE | 2850 | 0.273 | 25.366 | 10.77
PLATE | 2690 | 0.261 | 25.284 | 10.3

# IfcPlate: PL15*43 (414)
In: Undefined
Description: PL15*43; Material: STEEL/S355N (Z-15)
Tekla Common - Class: 10; Phase: 3; Top elevation: -0.030; Bottom elevation: -0.045
Tekla Quantity - Width: 15 mm; Height: 43 mm; Volume: 0 m3
PlateBaseQuantities - Width: 43 mm; NetArea: 0 m2; GrossArea: 0 m2; CrossSectionArea: 0 m2; NetVolume: 0 m3; GrossVolume: 0 m3
Name | Length (mm) | Net surface area (m2) | Area per tons (m2) | Gross footprint area (m2) | Weight (kg)
18 x PLATE | 87 | 0.011 | 25.638 | 0.003 | 0.43
18 x PLATE | 87 | 0.011 | 25.637 | 0.003 | 0.43
18 x PLATE | 100 | 0.012 | 25.256 | 0.004 | 0.49
36 x PLATE | 97 | 0.012 | 25.334 | 0.004 | 0.48
18 x PLATE | 60 | 0.008 | 26.955 | 0.002 | 0.29
18 x PLATE | 100 | 0.012 | 25.255 | 0.004 | 0.49
108 x PLATE | 60 | 0.008 | 26.954 | 0.002 | 0.29
180 x PLATE | 81 | 0.009 | 25.854 | 0.003 | 0.4

# IfcPlate: PL15*500, PLATE
In: Undefined
Description: PL15*500; Material: STEEL/S355N
Tekla Common - Class: 4; Phase: 7; Top elevation: -0.010; Bottom elevation: -0.079
Tekla Quantity - Length: 9430 mm; Width: 15 mm; Height: 500 mm; Net surface area: 9.681 m2; Area per tons: 17.534 m2; Gross footprint area: 0 m2; Volume: 0.07 m3; Weight: 552.16 kg
PlateBaseQuantities - Width: 500 mm; NetArea: 9.7 m2; GrossArea: 4.7 m2; CrossSectionArea: 0 m2; NetVolume: 0.1 m3; GrossVolume: 0.1 m3

# IfcPlate: PL15*79 (4)
In: Undefined
Description: PL15*79; Material: STEEL/S355N
Tekla Common - Class: 4; Phase: 5; Top elevation: -0.438; Bottom elevation: -0.453
Tekla Quantity - Width: 15 mm; Height: 78.8 mm; Net surface area: 0.039 m2; Area per tons: 22.933 m2; Gross footprint area: 0.015 m2; Volume: 0 m3; Weight: 1.71 kg
PlateBaseQuantities - Width: 78.8 mm; NetArea: 0 m2; GrossArea: 0 m2; CrossSectionArea: 0 m2; NetVolume: 0 m3; GrossVolume: 0 m3
Name | Length (mm)
2 x PLATE | 305.7
2 x PLATE | 305.8

# IfcPlate: PL15*83 (2)
In: Undefined
Description: PL15*83; Material: STEEL/S355N
Tekla Common - Class: 4; Phase: 5; Top elevation: -0.438; Bottom elevation: -0.453
Tekla Quantity - Length: 307.3 mm; Width: 15 mm; Height: 83.3 mm; Net surface area: 0.041 m2; Area per tons: 22.698 m2; Gross footprint area: 0.015 m2; Volume: 0 m3; Weight: 1.81 kg
PlateBaseQuantities - Width: 83.3 mm; NetArea: 0 m2; GrossArea: 0 m2; CrossSectionArea: 0 m2; NetVolume: 0 m3; GrossVolume: 0 m3

# IfcPlate: PL20*100 (6)
In: Undefined
Description: PL20*100; Material: STEEL/S355N
Tekla Common - Class: 4; Phase: 7; Top elevation: -1.458; Bottom elevation: -1.478
Tekla Quantity - Width: 20 mm; Height: 100 mm
PlateBaseQuantities - Width: 100 mm; GrossArea: 0.1 m2; CrossSectionArea: 0 m2; NetVolume: 0 m3; GrossVolume: 0 m3
Name | Length (mm) | Net surface area (m2) | Area per tons (m2) | Gross footprint area (m2) | Volume (m3) | Weight (kg) | NetArea (m2)
4 x PLATE | 550 | 0.136 | 15.75 | 0.055 | 0.001 | 8.64 | 0.1
2 x PLATE | 955 | 0.233 | 15.553 | 0.096 | 0.002 | 14.99 | 0.2

# IfcPlate: PL20*116 (6)
In: Undefined
Description: PL20*116; Material: STEEL/S355N
Tekla Common - Phase: 5; Top elevation: -0.570; Bottom elevation: -0.860
Tekla Quantity - Length: 290 mm; Width: 20 mm; Net surface area: 0.07 m2; Gross footprint area: 0.001 m2; Volume: 0.001 m3
PlateBaseQuantities - NetArea: 0.1 m2; GrossArea: 0 m2; CrossSectionArea: 0 m2; NetVolume: 0 m3; GrossVolume: 0 m3
Name | Class | Height (mm) = Width (mm) | Area per tons (m2) | Weight (kg)
2 x PLATE | 4 | 116 | 16.136 | 4.37
3 x PLATE | 130 | 115.7 | 16.143 | 4.35
PLATE | 130 | 116 | 16.136 | 4.37

# IfcPlate: PL20*129 (2)
In: Undefined
Description: PL20*129; Material: STEEL/S355N
Tekla Common - Class: 4; Phase: 10; Top elevation: -0.015; Bottom elevation: -0.146
Tekla Quantity - Length: 381.3 mm; Width: 20 mm; Height: 129.4 mm; Net surface area: 0.082 m2; Area per tons: 16.284 m2; Gross footprint area: 0.007 m2; Volume: 0.001 m3; Weight: 5.05 kg
PlateBaseQuantities - Width: 129.4 mm; NetArea: 0.1 m2; GrossArea: 0 m2; CrossSectionArea: 0 m2; NetVolume: 0 m3; GrossVolume: 0 m3

# IfcPlate: PL20*132 (30)
In: Undefined
Description: PL20*132; Material: STEEL/S355N
Tekla Common - Phase: 5
Tekla Quantity - Width: 20 mm; Height: 132 mm
PlateBaseQuantities - Width: 132 mm; CrossSectionArea: 0 m2; NetVolume: 0 m3; GrossVolume: 0 m3
Name | Class | Top elevation | Bottom elevation | Length (mm) | Net surface area (m2) | Area per tons (m2) | Gross footprint area (m2) | Volume (m3) | Weight (kg) | NetArea (m2) | GrossArea (m2)
12 x PLATE | 130 | -0.030 | -0.860 | 830 | 0.256 | 14.954 | 0.002 | 0.002 | 17.14 | 0.3 | 0.1
16 x PLATE | 4 | -0.030 | -0.280 | 250 | 0.057 | 16.703 | 0.002 | 0 | 3.39 | 0.1 | 0
2 x PLATE | 130 | -0.535 | -0.860 | 325 | 0.103 | 15.427 | 0.003 | 0.001 | 6.7 | 0.1 | 0

# IfcPlate: PL20*140 (2)
In: Undefined
Description: PL20*140; Material: STEEL/S355N
Tekla Common - Class: 5; Phase: 13; Top elevation: -0.360; Bottom elevation: -0.510
Tekla Quantity - Length: 150 mm; Width: 20 mm; Height: 140 mm; Net surface area: 0.031 m2; Area per tons: 18.747 m2; Gross footprint area: 0.003 m2; Volume: 0 m3; Weight: 1.65 kg
PlateBaseQuantities - Width: 140 mm; NetArea: 0 m2; GrossArea: 0 m2; CrossSectionArea: 0 m2; NetVolume: 0 m3; GrossVolume: 0 m3

# IfcPlate: PL20*155, PLATE
In: Undefined
Description: PL20*155; Material: STEEL/S355N
Tekla Common - Class: 4; Phase: 10; Top elevation: -0.005; Bottom elevation: -0.161
Tekla Quantity - Length: 8700 mm; Width: 20 mm; Height: 155 mm; Net surface area: 3.051 m2; Area per tons: 14.412 m2; Gross footprint area: 0 m2; Volume: 0.026 m3; Weight: 211.71 kg
PlateBaseQuantities - Width: 155 mm; NetArea: 3.1 m2; GrossArea: 1.3 m2; CrossSectionArea: 0 m2; NetVolume: 0 m3; GrossVolume: 0 m3

# IfcPlate: PL20*180 (56)
In: Undefined
Description: PL20*180
Tekla Quantity - Width: 20 mm; Volume: 0.001 m3
PlateBaseQuantities - NetArea: 0.1 m2; CrossSectionArea: 0 m2; NetVolume: 0 m3; GrossVolume: 0 m3
Name | Material | Class | Phase | Top elevation | Bottom elevation | Length (mm) | Height (mm) = Width (mm) | Net surface area (m2) | Area per tons (m2) | Gross footprint area (m2) | Weight (kg) | GrossArea (m2)
52 x PLATE | STEEL/S355N | 14 | 4 | -0.355 | -0.535 | 230 | 180 | 0.086 | 16.421 | 0.003 | 5.26 | 0
4 x HEISTÅRN | STEEL/Steel_Undefined | 3 | 6 | +2.127 | +1.694 | 433 | 180.1 | 0.108 | 16.581 | 0 | 6.54 | 0.1

# IfcPlate: PL20*204 (2)
In: Undefined
Description: PL20*204; Material: STEEL/S355N
Tekla Common - Class: 4; Phase: 10; Top elevation: -0.393; Bottom elevation: -0.413
Tekla Quantity - Length: 300 mm; Width: 20 mm; Height: 204 mm; Net surface area: 0.143 m2; Area per tons: 14.837 m2; Gross footprint area: 0.061 m2; Volume: 0.001 m3; Weight: 9.61 kg
PlateBaseQuantities - Width: 204 mm; NetArea: 0.1 m2; GrossArea: 0.1 m2; CrossSectionArea: 0 m2; NetVolume: 0 m3; GrossVolume: 0 m3

# IfcPlate: PL20*250 (2)
In: Undefined
Description: PL20*250; Material: STEEL/S355N
Tekla Common - Class: 4; Phase: 10; Top elevation: -0.627; Bottom elevation: -0.875
Tekla Quantity - Length: 300 mm; Width: 20 mm; Height: 250 mm; Net surface area: 0.144 m2; Area per tons: 14.728 m2; Gross footprint area: 0 m2; Volume: 0.001 m3; Weight: 9.8 kg
PlateBaseQuantities - Width: 250 mm; NetArea: 0.1 m2; GrossArea: 0.1 m2; CrossSectionArea: 0 m2; NetVolume: 0 m3; GrossVolume: 0 m3

# IfcPlate: PL20*300 (6)
In: Undefined
Description: PL20*300; Material: STEEL/S355N
Tekla Common - Class: 4; Phase: 10
Tekla Quantity - Width: 20 mm; Height: 300 mm
PlateBaseQuantities - Width: 300 mm; CrossSectionArea: 0 m2; NetVolume: 0 m3; GrossVolume: 0 m3
Name | Top elevation | Bottom elevation | Length (mm) | Net surface area (m2) | Area per tons (m2) | Gross footprint area (m2) | Volume (m3) | Weight (kg) | NetArea (m2) | GrossArea (m2)
2 x PLATE | -0.175 | -0.401 | 320 | 0.217 | 14.384 | 0 | 0.002 | 15.07 | 0.2 | 0.1
2 x PLATE | -0.408 | -0.885 | 533.6 | 0.353 | 14.066 | 0 | 0.003 | 25.13 | 0.3 | 0.2
2 x PLATE | -0.875 | -0.895 | 389 | 0.261 | 14.243 | 0.117 | 0.002 | 18.32 | 0.3 | 0.1

# IfcPlate: PL20*312 (2)
In: Undefined
Description: PL20*312; Material: STEEL/S355N
Tekla Common - Class: 4; Phase: 10; Top elevation: -0.065; Bottom elevation: -0.393
Tekla Quantity - Length: 411.9 mm; Width: 20 mm; Height: 311.6 mm; Net surface area: 0.187 m2; Area per tons: 14.642 m2; Gross footprint area: 0 m2; Volume: 0.002 m3; Weight: 12.76 kg
PlateBaseQuantities - Width: 311.6 mm; NetArea: 0.2 m2; GrossArea: 0.1 m2; CrossSectionArea: 0 m2; NetVolume: 0 m3; GrossVolume: 0 m3

# IfcPlate: PL20*338 (2)
In: Undefined
Description: PL20*338; Material: STEEL/S355N
Tekla Common - Class: 4; Phase: 10; Top elevation: -0.035; Bottom elevation: -0.373
Tekla Quantity - Length: 475.2 mm; Width: 20 mm; Height: 338 mm; Net surface area: 0.231 m2; Area per tons: 14.487 m2; Gross footprint area: 0.01 m2; Volume: 0.002 m3; Weight: 15.94 kg
PlateBaseQuantities - Width: 338 mm; NetArea: 0.2 m2; GrossArea: 0.2 m2; CrossSectionArea: 0 m2; NetVolume: 0 m3; GrossVolume: 0 m3

# IfcPlate: PL20*364 (9)
In: Undefined
Description: PL20*364; Material: STEEL/S355N
Tekla Common - Class: 4; Phase: 10; Top elevation: -0.015; Bottom elevation: -0.379
Tekla Quantity - Length: 844.4 mm; Width: 20 mm; Height: 364 mm; Net surface area: 0.506 m2; Area per tons: 14.291 m2; Gross footprint area: 0.01 m2; Volume: 0.005 m3; Weight: 35.4 kg
PlateBaseQuantities - Width: 364 mm; NetArea: 0.5 m2; GrossArea: 0.3 m2; CrossSectionArea: 0 m2; NetVolume: 0 m3; GrossVolume: 0 m3

# IfcPlate: PL20*500 (4)
In: Undefined
Description: PL20*500; Material: STEEL/Steel_Undefined
Tekla Common - Class: 3; Phase: 6; Top elevation: +6.010; Bottom elevation: +5.510
Tekla Quantity - Length: 1265 mm; Width: 20 mm; Height: 500 mm; Net surface area: 1.223 m2; Area per tons: 13.469 m2; Gross footprint area: 0.015 m2; Volume: 0.012 m3; Weight: 90.82 kg
PlateBaseQuantities - Width: 500 mm; NetArea: 1.3 m2; GrossArea: 0.6 m2; CrossSectionArea: 0 m2; NetVolume: 0 m3; GrossVolume: 0 m3

# IfcPlate: PL20*616 (2)
In: Undefined
Description: PL20*616; Material: STEEL/S355N
Tekla Common - Class: 4; Phase: 10; Top elevation: -0.035; Bottom elevation: -0.865
Tekla Quantity - Length: 830 mm; Width: 20 mm; Height: 615.9 mm; Net surface area: 0.866 m2; Area per tons: 13.529 m2; Gross footprint area: 0.005 m2; Volume: 0.008 m3; Weight: 64.04 kg
PlateBaseQuantities - Width: 615.9 mm; NetArea: 0.8 m2; GrossArea: 0.5 m2; CrossSectionArea: 0 m2; NetVolume: 0 m3; GrossVolume: 0 m3

# IfcPlate: PL20*617, PLATE
In: Undefined
Description: PL20*617; Material: STEEL/S355N
Tekla Common - Class: 4; Phase: 10; Top elevation: +0.005; Bottom elevation: -0.015
Tekla Quantity - Length: 8700 mm; Width: 20 mm; Height: 617 mm; Net surface area: 11.034 m2; Area per tons: 13.205 m2; Gross footprint area: 5.194 m2; Volume: 0.106 m3; Weight: 835.62 kg
PlateBaseQuantities - Width: 617 mm; NetArea: 11 m2; GrossArea: 5.4 m2; CrossSectionArea: 0 m2; NetVolume: 0.1 m3; GrossVolume: 0.1 m3

# IfcPlate: PL20*85 (6)
In: Undefined
Description: PL20*85; Material: STEEL/S355N
Tekla Common - Class: 4; Phase: 11; Top elevation: -0.025; Bottom elevation: -0.110
Tekla Quantity - Length: 120 mm; Width: 20 mm; Height: 85 mm; Net surface area: 0.03 m2; Area per tons: 17.859 m2; Gross footprint area: 0.002 m2; Volume: 0 m3; Weight: 1.6 kg
PlateBaseQuantities - Width: 85 mm; NetArea: 0 m2; GrossArea: 0 m2; CrossSectionArea: 0 m2; NetVolume: 0 m3; GrossVolume: 0 m3

# IfcPlate: PL25*220 (2)
In: Undefined
Description: PL25*220; Material: STEEL/S355N
Tekla Common - Class: 5; Phase: 13; Top elevation: -0.335; Bottom elevation: -0.555
Tekla Quantity - Length: 670 mm; Width: 25 mm; Height: 220 mm; Net surface area: 0.339 m2; Area per tons: 11.729 m2; Gross footprint area: 0.017 m2; Volume: 0.004 m3; Weight: 28.93 kg
PlateBaseQuantities - Width: 220 mm; NetArea: 0.3 m2; GrossArea: 0.1 m2; CrossSectionArea: 0 m2; NetVolume: 0 m3; GrossVolume: 0 m3

# IfcPlate: PL25*600 (2)
In: Undefined
Description: PL25*600; Material: STEEL/Steel_Undefined
Tekla Common - Class: 3; Phase: 6; Top elevation: +1.630; Bottom elevation: -2.300
Tekla Quantity - Length: 3930 mm; Width: 25 mm; Height: 600 mm; Net surface area: 4.942 m2; Area per tons: 10.681 m2; Gross footprint area: 0.015 m2; Volume: 0.059 m3; Weight: 462.76 kg
PlateBaseQuantities - Width: 600 mm; NetArea: 4.9 m2; GrossArea: 2.4 m2; CrossSectionArea: 0 m2; NetVolume: 0.1 m3; GrossVolume: 0.1 m3

# IfcPlate: PL25*627 (2)
In: Undefined
Description: PL25*627; Material: STEEL/S355N
Tekla Common - Class: 4; Phase: 10; Top elevation: -0.185; Bottom elevation: -0.875
Tekla Quantity - Length: 690 mm; Width: 25 mm; Height: 626.7 mm; Net surface area: 0.755 m2; Area per tons: 11.199 m2; Gross footprint area: 0.008 m2; Volume: 0.009 m3; Weight: 67.42 kg
PlateBaseQuantities - Width: 626.7 mm; NetArea: 0.8 m2; GrossArea: 0.3 m2; CrossSectionArea: 0 m2; NetVolume: 0 m3; GrossVolume: 0 m3

# IfcPlate: PL3*115 (126)
In: Undefined
Description: PL3*115; Material: STEEL/S355J2
Tekla Common - Class: 6; Phase: 3; Top elevation: -0.005; Bottom elevation: -0.120
Tekla Quantity - Length: 880 mm; Width: 3 mm; Height: 115 mm; Net surface area: 0.208 m2; Area per tons: 87.431 m2; Gross footprint area: 0.003 m2; Volume: 0 m3; Weight: 2.38 kg
PlateBaseQuantities - Width: 115 mm; NetArea: 0.2 m2; GrossArea: 0.1 m2; CrossSectionArea: 0 m2; NetVolume: 0 m3; GrossVolume: 0 m3

# IfcPlate: PL3*130 (576)
In: Undefined
Description: PL3*130; Material: STEEL/S355J2
Tekla Common - Class: 6; Phase: 3; Top elevation: -0.005; Bottom elevation: -0.135
Tekla Quantity - Length: 285 mm; Width: 3 mm; Height: 130 mm; Net surface area: 0.07 m2; Area per tons: 88.12 m2; Gross footprint area: 0.001 m2; Volume: 0 m3; Weight: 0.8 kg
PlateBaseQuantities - Width: 130 mm; NetArea: 0.1 m2; GrossArea: 0 m2; CrossSectionArea: 0 m2; NetVolume: 0 m3; GrossVolume: 0 m3

# IfcPlate: PL30*100 (2)
In: Undefined
Description: PL30*100; Material: STEEL/S355N
Tekla Common - Class: 4; Phase: 7; Top elevation: -0.688; Bottom elevation: -0.788
Tekla Quantity - Length: 959 mm; Width: 30 mm; Height: 100 mm; Net surface area: 0.244 m2; Area per tons: 11.335 m2; Gross footprint area: 0.025 m2; Volume: 0.003 m3; Weight: 21.53 kg
PlateBaseQuantities - Width: 100 mm; NetArea: 0.2 m2; GrossArea: 0.1 m2; CrossSectionArea: 0 m2; NetVolume: 0 m3; GrossVolume: 0 m3

# IfcPlate: PL30*1000 (3)
In: Undefined
Description: PL30*1000; Material: STEEL/S355N
Tekla Common - Class: 4; Phase: 11; Top elevation: +0.005; Bottom elevation: -0.025
Tekla Quantity - Width: 30 mm; Height: 1000 mm
PlateBaseQuantities - Width: 1000 mm; CrossSectionArea: 0 m2; NetVolume: 0.1 m3; GrossVolume: 0.1 m3
Name | Length (mm) | Net surface area (m2) | Area per tons (m2) | Gross footprint area (m2) | Volume (m3) | Weight (kg) | NetArea (m2) | GrossArea (m2)
PLATE | 3145 | 6.433 | 8.841 | 3.043 | 0.093 | 727.56 | 6.4 | 3.1
PLATE | 2990 | 6.117 | 8.845 | 2.892 | 0.088 | 691.61 | 6.1 | 3
PLATE | 3145 | 6.433 | 8.839 | 3.043 | 0.093 | 727.76 | 6.4 | 3.1

# IfcPlate: PL30*1025 (2)
In: Undefined
Description: PL30*1025; Material: STEEL/S355N (Z-25)
Tekla Common - Class: 4; Phase: 7; Top elevation: -1.028; Bottom elevation: -1.058
Tekla Quantity - Length: 1100 mm; Width: 30 mm; Height: 1025 mm; Net surface area: 2.382 m2; Area per tons: 8.973 m2; Gross footprint area: 1.127 m2; Volume: 0.034 m3; Weight: 265.53 kg
PlateBaseQuantities - Width: 1025 mm; NetArea: 2.4 m2; GrossArea: 1.1 m2; CrossSectionArea: 0 m2; NetVolume: 0 m3; GrossVolume: 0 m3

# IfcPlate: PL30*152 (2)
In: Undefined
Description: PL30*152; Material: STEEL/S355N
Tekla Common - Class: 4; Phase: 7; Top elevation: -0.901; Bottom elevation: -1.028
Tekla Quantity - Length: 779 mm; Width: 30 mm; Height: 152 mm; Net surface area: 0.293 m2; Area per tons: 10.495 m2; Gross footprint area: 0 m2; Volume: 0.004 m3; Weight: 27.9 kg
PlateBaseQuantities - Width: 152 mm; NetArea: 0.3 m2; GrossArea: 0.1 m2; CrossSectionArea: 0 m2; NetVolume: 0 m3; GrossVolume: 0 m3

# IfcPlate: PL30*165 (4)
In: Undefined
Description: PL30*165; Material: STEEL/S355N
Tekla Common - Class: 5; Phase: 13; Top elevation: +0.240; Bottom elevation: -0.345
Tekla Quantity - Length: 585 mm; Width: 30 mm; Height: 165 mm; Net surface area: 0.233 m2; Area per tons: 10.868 m2; Gross footprint area: 0.003 m2; Volume: 0.003 m3; Weight: 21.47 kg
PlateBaseQuantities - Width: 165 mm; NetArea: 0.2 m2; GrossArea: 0.1 m2; CrossSectionArea: 0 m2; NetVolume: 0 m3; GrossVolume: 0 m3

# IfcPlate: PL30*200 (4)
In: Undefined
Description: PL30*200; Material: STEEL/Steel_Undefined
Tekla Common - Class: 3; Phase: 6; Top elevation: +5.760; Bottom elevation: +5.300
Tekla Quantity - Length: 460 mm; Width: 30 mm; Height: 200 mm; Net surface area: 0.212 m2; Area per tons: 10.287 m2; Gross footprint area: 0.006 m2; Volume: 0.003 m3; Weight: 20.62 kg
PlateBaseQuantities - Width: 200 mm; NetArea: 0.2 m2; GrossArea: 0.1 m2; CrossSectionArea: 0 m2; NetVolume: 0 m3; GrossVolume: 0 m3

# IfcPlate: PL30*210 (6)
In: Undefined
Description: PL30*210; Material: STEEL/S355N
Tekla Common - Class: 4; Phase: 7; Top elevation: -0.818; Bottom elevation: -1.028
Tekla Quantity - Width: 30 mm; Height: 210 mm
PlateBaseQuantities - Width: 210 mm; CrossSectionArea: 0 m2; NetVolume: 0 m3; GrossVolume: 0 m3
Name | Length (mm) | Net surface area (m2) | Area per tons (m2) | Gross footprint area (m2) | Volume (m3) | Weight (kg) | NetArea (m2) | GrossArea (m2)
4 x PLATE | 445 | 0.193 | 10.461 | 0.007 | 0.002 | 18.45 | 0.2 | 0.1
2 x PLATE | 779 | 0.387 | 10.033 | 0.023 | 0.005 | 38.53 | 0.3 | 0.2

# IfcPlate: PL30*235 (2)
In: Undefined
Description: PL30*235; Material: STEEL/S355N (Z-25)
Tekla Common - Class: 4; Phase: 7; Top elevation: -0.788; Bottom elevation: -0.818
Tekla Quantity - Length: 979 mm; Width: 30 mm; Height: 235 mm; Net surface area: 0.524 m2; Area per tons: 9.831 m2; Gross footprint area: 0.215 m2; Volume: 0.007 m3; Weight: 53.32 kg
PlateBaseQuantities - Width: 235 mm; NetArea: 0.5 m2; GrossArea: 0.2 m2; CrossSectionArea: 0 m2; NetVolume: 0 m3; GrossVolume: 0 m3

# IfcPlate: PL30*300 (4)
In: Undefined
Description: PL30*300; Material: STEEL/S355N
Tekla Common - Class: 4; Phase: 10
Tekla Quantity - Width: 30 mm; Height: 300 mm
PlateBaseQuantities - Width: 300 mm; NetArea: 0.3 m2; CrossSectionArea: 0 m2; NetVolume: 0 m3; GrossVolume: 0 m3
Name | Top elevation | Bottom elevation | Length (mm) | Net surface area (m2) | Area per tons (m2) | Gross footprint area (m2) | Volume (m3) | Weight (kg) | GrossArea (m2)
2 x PLATE | -0.410 | -0.879 | 515 | 0.358 | 9.837 | 0 | 0.005 | 36.38 | 0.2
2 x PLATE | -0.865 | -0.895 | 393 | 0.277 | 9.99 | 0.118 | 0.004 | 27.77 | 0.1

# IfcPlate: PL30*460 (2)
In: Undefined
Description: PL30*460; Material: STEEL/S355N
Tekla Common - Class: 5; Phase: 13; Top elevation: +0.240; Bottom elevation: -1.165
Tekla Quantity - Length: 1405 mm; Width: 30 mm; Height: 460 mm; Net surface area: 1.212 m2; Area per tons: 9.475 m2; Gross footprint area: 0.007 m2; Volume: 0.016 m3; Weight: 127.88 kg
PlateBaseQuantities - Width: 460 mm; NetArea: 1.3 m2; GrossArea: 0.6 m2; CrossSectionArea: 0 m2; NetVolume: 0 m3; GrossVolume: 0 m3

# IfcPlate: PL30*625 (2)
In: Undefined
Description: PL30*625; Material: STEEL/S355N
Tekla Common - Class: 5; Phase: 13; Top elevation: +0.240; Bottom elevation: -1.470
Tekla Quantity - Length: 1710 mm; Width: 30 mm; Height: 625 mm; Net surface area: 1.878 m2; Area per tons: 9.147 m2; Gross footprint area: 0.007 m2; Volume: 0.026 m3; Weight: 205.37 kg
PlateBaseQuantities - Width: 625 mm; NetArea: 1.9 m2; GrossArea: 1.1 m2; CrossSectionArea: 0 m2; NetVolume: 0 m3; GrossVolume: 0 m3

# IfcPlate: PL30*70 (4)
In: Undefined
Description: PL30*70; Material: STEEL/S355N
Tekla Common - Class: 4; Phase: 7; Top elevation: -0.818; Bottom elevation: -0.848
Tekla Quantity - Length: 235 mm; Width: 30 mm; Height: 70 mm; Net surface area: 0.051 m2; Area per tons: 13.216 m2; Gross footprint area: 0.016 m2; Volume: 0 m3; Weight: 3.87 kg
PlateBaseQuantities - Width: 70 mm; NetArea: 0.1 m2; GrossArea: 0 m2; CrossSectionArea: 0 m2; NetVolume: 0 m3; GrossVolume: 0 m3

# IfcPlate: PL30*700 (2)
In: Undefined
Description: PL30*700; Material: STEEL/S355N
Tekla Common - Class: 4; Phase: 7; Top elevation: -1.028; Bottom elevation: -1.058
Tekla Quantity - Length: 1025 mm; Width: 30 mm; Height: 700 mm; Net surface area: 1.538 m2; Area per tons: 9.105 m2; Gross footprint area: 0.717 m2; Volume: 0.022 m3; Weight: 168.97 kg
PlateBaseQuantities - Width: 700 mm; NetArea: 1.4 m2; GrossArea: 0.6 m2; CrossSectionArea: 0 m2; NetVolume: 0 m3; GrossVolume: 0 m3

# IfcPlate: PL30*830, PLATE
In: Undefined
Description: PL30*830; Material: STEEL/S355N
Tekla Common - Class: 4; Phase: 11; Top elevation: -0.045; Bottom elevation: -0.875
Tekla Quantity - Length: 9800 mm; Width: 30 mm; Height: 830 mm; Net surface area: 16.558 m2; Area per tons: 8.879 m2; Gross footprint area: 0.294 m2; Volume: 0.238 m3; Weight: 1864.88 kg
PlateBaseQuantities - Width: 830 mm; NetArea: 16.6 m2; GrossArea: 8.1 m2; CrossSectionArea: 0 m2; NetVolume: 0.2 m3; GrossVolume: 0.2 m3

# IfcPlate: PL30*846 (4)
In: Undefined
Description: PL30*846; Material: STEEL/S355N
Tekla Common - Class: 4; Phase: 5; Top elevation: -0.029; Bottom elevation: -0.875
Tekla Quantity - Length: 800 mm; Width: 30 mm; Height: 846 mm; Net surface area: 1.442 m2; Area per tons: 9.105 m2; Gross footprint area: 0.024 m2; Volume: 0.02 m3; Weight: 158.33 kg
PlateBaseQuantities - Width: 846 mm; NetArea: 1.4 m2; GrossArea: 0.6 m2; CrossSectionArea: 0 m2; NetVolume: 0 m3; GrossVolume: 0 m3

# IfcPlate: PL40*174 (2)
In: Undefined
Description: PL40*174; Material: MISCELLANEOUS/UHMW-PE
Tekla Common - Class: 6; Phase: 13; Top elevation: -0.358; Bottom elevation: -0.532
Tekla Quantity - Length: 625 mm; Width: 40 mm; Height: 174 mm; Net surface area: 0.295 m2; Area per tons: 0 m2; Gross footprint area: 0.016 m2; Volume: 0.004 m3; Weight: 0 kg
PlateBaseQuantities - Width: 174 mm; NetArea: 0.3 m2; GrossArea: 0.1 m2; CrossSectionArea: 0 m2; NetVolume: 0 m3; GrossVolume: 0 m3

# IfcPlate: PL40*180 (26)
In: Undefined
Description: PL40*180; Material: STEEL/S355N (Z-25)
Tekla Common - Class: 4; Phase: 5; Top elevation: -0.355; Bottom elevation: -0.535
Tekla Quantity - Width: 40 mm; Height: 180 mm
PlateBaseQuantities - Width: 180 mm; NetArea: 0.2 m2; GrossArea: 0.1 m2; CrossSectionArea: 0 m2; NetVolume: 0 m3; GrossVolume: 0 m3
Name | Length (mm) | Net surface area (m2) | Area per tons (m2) | Gross footprint area (m2) | Volume (m3) | Weight (kg)
6 x PLATE | 367 | 0.166 | 9.091 | 0.01 | 0.002 | 18.27
2 x PLATE | 569.2 | 0.25 | 8.626 | 0.019 | 0.004 | 28.93
2 x PLATE | 549.5 | 0.243 | 8.592 | 0.019 | 0.004 | 28.28
2 x PLATE | 545.5 | 0.242 | 8.594 | 0.019 | 0.004 | 28.11
2 x PLATE | 553 | 0.243 | 8.608 | 0.019 | 0.004 | 28.25
4 x PLATE | 367 | 0.163 | 9.045 | 0.01 | 0.002 | 17.99
2 x PLATE | 552.8 | 0.243 | 8.611 | 0.019 | 0.004 | 28.23
2 x PLATE | 553.1 | 0.243 | 8.608 | 0.019 | 0.004 | 28.25
2 x PLATE | 546.7 | 0.242 | 8.592 | 0.019 | 0.004 | 28.16
2 x PLATE | 548.9 | 0.243 | 8.594 | 0.019 | 0.004 | 28.25

# IfcPlate: PL40*208 (2)
In: Undefined
Description: PL40*208; Material: STEEL/S355N
Tekla Common - Class: 4; Phase: 10; Top elevation: -0.373; Bottom elevation: -0.413
Tekla Quantity - Length: 300 mm; Width: 40 mm; Height: 208 mm; Net surface area: 0.165 m2; Area per tons: 8.444 m2; Gross footprint area: 0.062 m2; Volume: 0.002 m3; Weight: 19.59 kg
PlateBaseQuantities - Width: 208 mm; NetArea: 0.2 m2; GrossArea: 0.1 m2; CrossSectionArea: 0 m2; NetVolume: 0 m3; GrossVolume: 0 m3

# IfcPlate: PL40*300 (12)
In: Undefined
Description: PL40*300
Tekla Quantity - Width: 40 mm; Height: 300 mm
PlateBaseQuantities - Width: 300 mm; CrossSectionArea: 0 m2; NetVolume: 0 m3; GrossVolume: 0 m3
Name | Material | Class | Phase | Top elevation | Bottom elevation | Length (mm) | Net surface area (m2) | Area per tons (m2) | Gross footprint area (m2) | Volume (m3) | Weight (kg) | NetArea (m2) | GrossArea (m2)
2 x PLATE | STEEL/S355N | 4 | 10 | -0.035 | -0.386 | 451.1 | 0.323 | 7.888 | 0.015 | 0.005 | 40.97 | 0.3 | 0.1
PLATE | STEEL/S355N | 4 | 10 | +0.005 | -0.035 | 986 | 0.691 | 7.477 | 0.296 | 0.012 | 92.42 | 0.8 | 0.3
2 x PLATE | STEEL/S355N (Z-25) | 4 | 10 | -0.020 | -0.875 | 855 | 0.605 | 7.517 | 0.012 | 0.009 | 80.54 | 0.6 | 0.3
2 x PLATE | STEEL/S355N (Z-25) | 4 | 10 | -0.020 | -0.895 | 875 | 0.619 | 7.51 | 0.012 | 0.011 | 82.43 | 0.6 | 0.3
4 x PLATE | STEEL/S355N (Z-25) | 2 | 5 | -0.020 | -0.875 | 855 | 0.605 | 7.517 | 0.012 | 0.009 | 80.54 | 0.6 | 0.3
PLATE | STEEL/S355N | 4 | 10 | +0.005 | -0.035 | 986 | 0.691 | 7.477 | 0.296 | 0.012 | 92.42 | 0.6 | 0.3

# IfcPlate: PL40*600 (2)
In: Undefined
Description: PL40*600; Material: STEEL/Steel_Undefined
Tekla Common - Class: 3; Phase: 6; Top elevation: +1.630; Bottom elevation: -2.300
Tekla Quantity - Length: 3930 mm; Width: 40 mm; Height: 600 mm; Net surface area: 5.153 m2; Area per tons: 7.042 m2; Gross footprint area: 0.024 m2; Volume: 0.093 m3; Weight: 731.76 kg
PlateBaseQuantities - Width: 600 mm; NetArea: 5.2 m2; GrossArea: 2.4 m2; CrossSectionArea: 0 m2; NetVolume: 0.1 m3; GrossVolume: 0.1 m3

# IfcPlate: PL5*100 (20)
In: Undefined
Description: PL5*100; Material: STEEL/S355J2
Tekla Common - Class: 11; Phase: 8; Top elevation: -0.855; Bottom elevation: -0.860
Tekla Quantity - Length: 120 mm; Width: 5 mm; Height: 100 mm; Net surface area: 0.026 m2; Area per tons: 55.626 m2; Gross footprint area: 0.012 m2; Volume: 0 m3; Weight: 0.48 kg
PlateBaseQuantities - Width: 100 mm; NetArea: 0 m2; GrossArea: 0 m2; CrossSectionArea: 0 m2; NetVolume: 0 m3; GrossVolume: 0 m3

# IfcPlate: PL5*120 (9)
In: Undefined
Description: PL5*120; Material: STEEL/S355J2
Tekla Common - Class: 4; Phase: 3; Top elevation: -0.000; Bottom elevation: -0.120
Tekla Quantity - Length: 878 mm; Width: 5 mm; Height: 120 mm; Net surface area: 0.221 m2; Area per tons: 53.369 m2; Gross footprint area: 0.004 m2; Volume: 0.001 m3; Weight: 4.14 kg
PlateBaseQuantities - Width: 120 mm; NetArea: 0.2 m2; GrossArea: 0.1 m2; CrossSectionArea: 0 m2; NetVolume: 0 m3; GrossVolume: 0 m3

# IfcPlate: PL5*130 (4)
In: Undefined
Description: PL5*130; Material: STEEL/S355N
Tekla Common - Class: 4; Phase: 9
Tekla Quantity - Length: 178.9 mm; Width: 5 mm; Height: 130 mm; Net surface area: 0.049 m2; Area per tons: 54.199 m2; Gross footprint area: 0 m2; Volume: 0 m3; Weight: 0.9 kg
PlateBaseQuantities - Width: 130 mm; NetArea: 0 m2; GrossArea: 0 m2; CrossSectionArea: 0 m2; NetVolume: 0 m3; GrossVolume: 0 m3
Name | Top elevation | Bottom elevation
3 x PLATE | +0.155 | +0.025
PLATE | +0.145 | +0.015

# IfcPlate: PL5*470 (9)
In: Undefined
Description: PL5*470; Material: STEEL/S355J2
Tekla Common - Class: 4; Phase: 3; Top elevation: +0.005; Bottom elevation: -0.000
Tekla Quantity - Length: 878 mm; Width: 5 mm; Height: 470 mm; Net surface area: 0.83 m2; Area per tons: 51.916 m2; Gross footprint area: 0.407 m2; Volume: 0.002 m3; Weight: 15.98 kg
PlateBaseQuantities - Width: 470 mm; NetArea: 0.8 m2; GrossArea: 0.5 m2; CrossSectionArea: 0 m2; NetVolume: 0 m3; GrossVolume: 0 m3

# IfcPlate: PL5*88 (20)
In: Undefined
Description: PL5*88; Material: STEEL/S355J2
Tekla Common - Class: 11; Phase: 8; Top elevation: +1.015; Bottom elevation: +1.010
Tekla Quantity - Length: 88 mm; Width: 5 mm; Height: 88 mm; Net surface area: 0.016 m2; Area per tons: 56.436 m2; Gross footprint area: 0.007 m2; Volume: 0 m3; Weight: 0.29 kg
PlateBaseQuantities - Width: 88 mm; NetArea: 0 m2; GrossArea: 0 m2; CrossSectionArea: 0 m2; NetVolume: 0 m3; GrossVolume: 0 m3

# IfcPlate: PL50*130 (2)
In: Undefined
Description: PL50*130; Material: MISCELLANEOUS/NULLVEKT
Tekla Common - Class: 6; Phase: 100; Top elevation: -0.030; Bottom elevation: -0.160
Tekla Quantity - Length: 300 mm; Width: 50 mm; Height: 130 mm; Net surface area: 0.121 m2; Area per tons: 0 m2; Gross footprint area: 0.015 m2; Volume: 0.002 m3; Weight: 0 kg
PlateBaseQuantities - Width: 130 mm; NetArea: 0.1 m2; GrossArea: 0 m2; CrossSectionArea: 0 m2; NetVolume: 0 m3; GrossVolume: 0 m3

# IfcPlate: PL50*150 (2)
In: Undefined
Description: PL50*150; Material: STEEL/Steel_Undefined
Tekla Common - Class: 3; Phase: 6; Top elevation: +0.205; Bottom elevation: +0.055
Tekla Quantity - Length: 150 mm; Width: 50 mm; Height: 150 mm; Net surface area: 0.067 m2; Area per tons: 11.7 m2; Gross footprint area: 0.004 m2; Volume: 0.001 m3; Weight: 5.71 kg
PlateBaseQuantities - Width: 150 mm; NetArea: 0.1 m2; GrossArea: 0 m2; CrossSectionArea: 0 m2; NetVolume: 0 m3; GrossVolume: 0 m3

# IfcPlate: PL8*30 (96)
In: Undefined
Description: PL8*30; Material: STEEL/S355J2
Tekla Common - Class: 130; Phase: 9
Tekla Quantity - Length: 52 mm; Width: 8 mm; Height: 30 mm; Net surface area: 0.004 m2; Area per tons: 44.979 m2; Gross footprint area: 0 m2; Volume: 0 m3; Weight: 0.1 kg
PlateBaseQuantities - Width: 30 mm; NetArea: 0 m2; GrossArea: 0 m2; CrossSectionArea: 0 m2; NetVolume: 0 m3; GrossVolume: 0 m3
Name | Top elevation | Bottom elevation
48 x PLATE | +0.367 | +0.315
48 x PLATE | +0.927 | +0.875

# IfcPlate: PL80*250 (2)
In: Undefined
Description: PL80*250; Material: STEEL/Steel_Undefined
Tekla Common - Class: 3; Phase: 6; Top elevation: +5.499; Bottom elevation: +5.249
Tekla Quantity - Length: 180 mm; Width: 80 mm; Height: 250 mm; Net surface area: 0.156 m2; Area per tons: 6.739 m2; Gross footprint area: 0 m2; Volume: 0.003 m3; Weight: 23.09 kg
PlateBaseQuantities - Width: 250 mm; NetArea: 0.2 m2; GrossArea: 0 m2; CrossSectionArea: 0 m2; NetVolume: 0 m3; GrossVolume: 0 m3

# IfcReinforcingBar (2)
In: Undefined
NominalDiameter: 16 mm; CrossSectionArea: 0 m2; Material: B500NC
Tekla Reinforcement - General - Phase: 7; Cast unit mark: LK-4; Spacing exact: 1*236 + 22*400 + 1*236; Spacing target: 235.5 mm; Group type: 0; Name: ARMERING
Tekla Reinforcement - Bending List - a: 400 mm; Weight total in group: 15.8 kg; Weight: 0.63 kg; Length: 400 mm; Shape: 00; Size: 16; Grade: B500NC; Number of bars in group: 25; Group position number: P10

# IfcSlab: 1160*227 (2)
In: Undefined
Description: 1160*227; Material: CONCRETE/B35
Tekla Common - Class: 1; Phase: 14; Top elevation: -1.058; Bottom elevation: -1.285
Tekla Quantity - Length: 1200 mm; Width: 1160 mm; Height: 226.6 mm; Net surface area: 3.756 m2; Area per tons: 5.463 m2; Gross footprint area: 1.392 m2; Volume: 0.286 m3; Weight: 687.54 kg
SlabBaseQuantities - Width: 1160 mm; NetArea: 1.4 m2; NetVolume: 0.3 m3; NetWeight: 687.5 kg

# IfcSlab: 12000*651, LANDKAR
In: Undefined
Description: 12000*651; Material: CONCRETE/B35
Tekla Common - Class: 1; Phase: 14; Top elevation: -0.009; Bottom elevation: -1.985
Tekla Quantity - Length: 1976 mm; Width: 12000 mm; Height: 651 mm; Net surface area: 64.827 m2; Area per tons: 1.785 m2; Gross footprint area: 1.8 m2; Volume: 15.133 m3; Weight: 36320.3 kg
SlabBaseQuantities - Width: 12000 mm; NetArea: 1.8 m2; NetVolume: 15.1 m3; NetWeight: 36320.3 kg

# IfcSlab: 12000*742, LANDKAR
In: Undefined
Description: 12000*742; Material: CONCRETE/B35
Tekla Common - Class: 1; Phase: 14; Top elevation: -1.243; Bottom elevation: -1.985
Tekla Quantity - Length: 1425 mm; Width: 12000 mm; Height: 742 mm; Net surface area: 53.462 m2; Area per tons: 1.817 m2; Gross footprint area: 0 m2; Volume: 12.261 m3; Weight: 29425.6 kg
SlabBaseQuantities - Width: 12000 mm; NetArea: 0 m2; NetVolume: 12.3 m3; NetWeight: 29425.6 kg

# IfcSlab: 900*227 (2)
In: Undefined
Description: 900*227; Material: CONCRETE/B35
Tekla Common - Class: 1; Phase: 14; Top elevation: -1.058; Bottom elevation: -1.285
Tekla Quantity - Length: 1200 mm; Width: 900 mm; Height: 226.6 mm; Net surface area: 3.025 m2; Area per tons: 5.671 m2; Gross footprint area: 1.08 m2; Volume: 0.222 m3; Weight: 533.43 kg
SlabBaseQuantities - Width: 900 mm; NetArea: 1.1 m2; NetVolume: 0.2 m3; NetWeight: 533.4 kg
